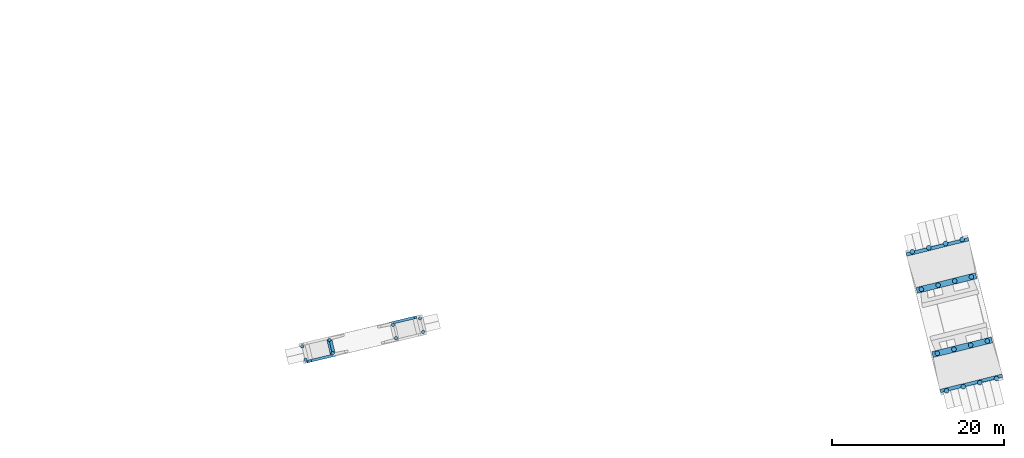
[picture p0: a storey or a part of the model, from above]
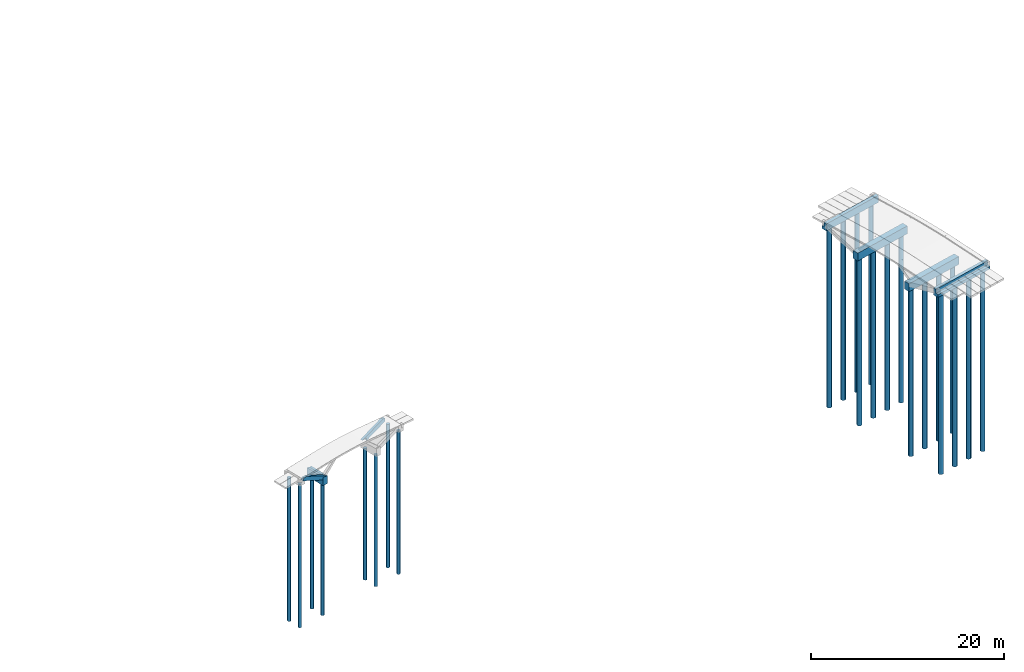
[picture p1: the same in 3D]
Properties of the parts of a building model (IFC2X3), part 1 of 2

# File
Description: ViewDefinition [CoordinationView_V2.0, QuantityTakeOffAddOnView]
File name: 319-150
Time: 2020-09-15T14:20:07
Written by: The EXPRESS Data Manager Version 5.02.0100.07 : 28 Aug 2013
Made in: 20190731_1515(x64) - Exporter 20.1.1.1 - Alternate UI 20.1.1.1
Comment: STEP Physical File produced by: The EXPRESS Data Manager Version 5.02.0100.07 : 28 Aug 2013 * Module: EDMstepFileFactory/EDMstandAlone * Creation date: Tue Sep 15 14:20:07 2020 * Host: PBT03-246 * Database: C:\Users\jeshol\AppData\Local\Temp\80c4dca2-110f-446d-8571-baf07fbfbc19\114c5863-edfc-40fc-962f-66e0f54f50cc\ifc * Database version: 5507 * Database creation date: Tue Sep 15 14:19:58 2020 * Schema: IFC2X3 * Model: DataRepository.ifc * Model creation date: Tue Sep 15 14:19:59 2020 * Header model: DataRepository.ifc_HeaderModel * Header model creation date: Tue Sep 15 14:19:59 2020 * EDMuser: sdai-user * EDMgroup: sdai-group * License ID and type: 5605 : Permanent license. Expiry date: * EDMstepFileFactory options: 020000

# IfcProject, 319-150
LongName: Bruggen Achterburggracht Machinesloot; Phase: Technisch Ontwerp

# IfcSite, Bruggen Achterburggracht Machinesloot
RefLatitude: 52, 22, 22, 799999; RefLongitude: 4, 53, 41, 279999; RefElevation: 0 mm

# IfcBuilding, Bruggen Achterburggracht Machinesloot
LongName: Bruggen Achterburggracht Machinesloot
Pset_Pieters_project informatie - Project Name: Bruggen Achterburggracht Machinesloot; Project Number: 319-150; Client Name: Gemeente Langedijk; Project Status: Technisch Ontwerp; Project Issue Date: 15-09-2020; model van: Pieters Bouwtechniek Delft; model status: Constructiefmodel; website: www.pietersbouwtechniek.nl; projectleider: S. Janssen; modelleur: Pieters Bouwtechniek Delft
Pset_ProductRequirements - Category: Project Information
Pset_BuildingCommon - NumberOfStoreys: 1

# IfcBuildingStorey: Level:PBT_level, 00 begane grond
In: Bruggen Achterburggracht Machinesloot
LongName: NAP; Elevation: 2.70717e-13 mm
Pset_AirSideSystemInformation - Name: palenplan
Pset_ProductRequirements - Name: palenplan; Category: Levels

# IfcBuildingElementProxy: Brug 2 kolom, Brug 2 kolom1:Brug 2 kolom:1546321
In: 00 begane grond
Type - Material: 00_PBT_MAT_beton t.p.g.
Type - Pset_BuildingElementProxyCommon - Reference: Brug 2 kolom1:Brug 2 kolom
Type - Pset_ProductRequirements - Category: Structural Framing
Type - Pset_QuantityTakeOff - Reference: Brug 2 kolom1:Brug 2 kolom
Pset_BuildingElementProxyCommon - sets with these values: 2
Phasing - Phase Created: Nieuw
Pset_Pieters - Naam: Brug 2 kolom1: Brug 2 kolom; Type: Brug 2 kolom1: Brug 2 kolom; Fase: gecreeerd: Nieuw

# IfcBuildingElementProxy: Brug 2 kolom, Brug 2 kolom2:Brug 2 kolom:1549490
In: 00 begane grond
Type - Material: 00_PBT_MAT_beton t.p.g.
Type - Pset_BuildingElementProxyCommon - Reference: Brug 2 kolom2:Brug 2 kolom
Type - Pset_ProductRequirements - Category: Structural Framing
Type - Pset_QuantityTakeOff - Reference: Brug 2 kolom2:Brug 2 kolom
Pset_BuildingElementProxyCommon - sets with these values: 2
Phasing - Phase Created: Nieuw
Pset_Pieters - Naam: Brug 2 kolom2: Brug 2 kolom; Type: Brug 2 kolom2: Brug 2 kolom; Fase: gecreeerd: Nieuw

# IfcBuildingElementProxy: Brug 2 kolom, Brug 2 kolom3:Brug 2 kolom:1563801
In: 00 begane grond
Type - Material: 00_PBT_MAT_beton t.p.g.
Type - Pset_BuildingElementProxyCommon - Reference: Brug 2 kolom3:Brug 2 kolom
Type - Pset_ProductRequirements - Category: Structural Framing
Type - Pset_QuantityTakeOff - Reference: Brug 2 kolom3:Brug 2 kolom
Pset_BuildingElementProxyCommon - sets with these values: 2
Phasing - Phase Created: Nieuw
Pset_Pieters - Naam: Brug 2 kolom3: Brug 2 kolom; Type: Brug 2 kolom3: Brug 2 kolom; Fase: gecreeerd: Nieuw

# IfcBuildingElementProxy: Brug 2 kolom, Brug 2 kolom4:Brug 2 kolom:1563828
In: 00 begane grond
Type - Material: 00_PBT_MAT_beton t.p.g.
Type - Pset_BuildingElementProxyCommon - Reference: Brug 2 kolom4:Brug 2 kolom
Type - Pset_ProductRequirements - Category: Structural Framing
Type - Pset_QuantityTakeOff - Reference: Brug 2 kolom4:Brug 2 kolom
Pset_BuildingElementProxyCommon - sets with these values: 2
Phasing - Phase Created: Nieuw
Pset_Pieters - Naam: Brug 2 kolom4: Brug 2 kolom; Type: Brug 2 kolom4: Brug 2 kolom; Fase: gecreeerd: Nieuw

# IfcBuildingElementProxy: Brug 2 wand, Brug 2 wand1:Brug 2 wand:1549459
In: 00 begane grond
Type - Material: 00_PBT_MAT_beton t.p.g.
Type - Pset_BuildingElementProxyCommon - Reference: Brug 2 wand1:Brug 2 wand
Type - Pset_ProductRequirements - Category: Structural Framing
Type - Pset_QuantityTakeOff - Reference: Brug 2 wand1:Brug 2 wand
Pset_BuildingElementProxyCommon - sets with these values: 2
Phasing - Phase Created: Nieuw
Pset_Pieters - Naam: Brug 2 wand1: Brug 2 wand; Type: Brug 2 wand1: Brug 2 wand; Fase: gecreeerd: Nieuw; Structural Material: 00_PBT_MAT_beton t.p.g.

# IfcBuildingElementProxy: Brug 2 wand, Brug 2 wand:Brug 2 wand:1545229
In: 00 begane grond
Type - Material: 00_PBT_MAT_beton t.p.g.
Type - Pset_BuildingElementProxyCommon - Reference: Brug 2 wand:Brug 2 wand
Type - Pset_ProductRequirements - Category: Structural Framing
Type - Pset_QuantityTakeOff - Reference: Brug 2 wand:Brug 2 wand
Pset_BuildingElementProxyCommon - sets with these values: 2
Phasing - Phase Created: Nieuw
Pset_Pieters - Naam: Brug 2 wand: Brug 2 wand; Type: Brug 2 wand: Brug 2 wand; Fase: gecreeerd: Nieuw; Structural Material: 00_PBT_MAT_beton t.p.g.

# IfcBuildingElementProxy: Brug 4 kolom/wand, Brug 4 kolom/wand1:Brug 4 kolom/wand:1635152
In: 00 begane grond
Type - Material: 00_PBT_MAT_beton t.p.g.
Type - Pset_BuildingElementProxyCommon - Reference: Brug 4 kolom/wand1:Brug 4 kolom/wand
Type - Pset_ProductRequirements - Category: Structural Framing
Type - Pset_QuantityTakeOff - Reference: Brug 4 kolom/wand1:Brug 4 kolom/wand
Pset_BuildingElementProxyCommon - sets with these values: 2
Phasing - Phase Created: Nieuw
Pset_Pieters - Naam: Brug 4 kolom/wand1: Brug 4 kolom/wand; Type: Brug 4 kolom/wand1: Brug 4 kolom/wand; Fase: gecreeerd: Nieuw

# IfcBuildingElementProxy: Brug 4 kolom/wand, Brug 4 kolom/wand2:Brug 4 kolom/wand:1885352
In: 00 begane grond
Type - Material: 00_PBT_MAT_beton t.p.g.
Type - Pset_BuildingElementProxyCommon - Reference: Brug 4 kolom/wand2:Brug 4 kolom/wand
Type - Pset_ProductRequirements - Category: Structural Framing
Type - Pset_QuantityTakeOff - Reference: Brug 4 kolom/wand2:Brug 4 kolom/wand
Pset_BuildingElementProxyCommon - sets with these values: 2
Phasing - Phase Created: Nieuw
Pset_Pieters - Naam: Brug 4 kolom/wand2: Brug 4 kolom/wand; Type: Brug 4 kolom/wand2: Brug 4 kolom/wand; Fase: gecreeerd: Nieuw

# IfcBuildingElementProxy: Brug 4 kolom/wand, Brug 4 kolom/wand:Brug 4 kolom/wand:1607215
In: 00 begane grond
Type - Material: 00_PBT_MAT_beton t.p.g.
Type - Pset_BuildingElementProxyCommon - Reference: Brug 4 kolom/wand:Brug 4 kolom/wand
Type - Pset_ProductRequirements - Category: Structural Framing
Type - Pset_QuantityTakeOff - Reference: Brug 4 kolom/wand:Brug 4 kolom/wand
Pset_BuildingElementProxyCommon - sets with these values: 2
Phasing - Phase Created: Nieuw
Pset_Pieters - Naam: Brug 4 kolom/wand: Brug 4 kolom/wand; Type: Brug 4 kolom/wand: Brug 4 kolom/wand; Fase: gecreeerd: Nieuw

# IfcBuildingElementProxy: brug 1 vleugelwand, brug 1 vleugelwand2:brug 1 vleugelwand:1730079
In: 00 begane grond
Type - Material: 00_PBT_MAT_beton t.p.g.
Type - Pset_BuildingElementProxyCommon - Reference: brug 1 vleugelwand2:brug 1 vleugelwand
Type - Pset_ProductRequirements - Category: Structural Framing
Type - Pset_QuantityTakeOff - Reference: brug 1 vleugelwand2:brug 1 vleugelwand
Pset_BuildingElementProxyCommon - sets with these values: 2
Phasing - Phase Created: Nieuw
Pset_Pieters - Naam: brug 1 vleugelwand2: brug 1 vleugelwand; Type: brug 1 vleugelwand2: brug 1 vleugelwand; Fase: gecreeerd: Nieuw; Structural Material: 00_PBT_MAT_beton t.p.g.

# IfcBuildingElementProxy: brug 1 vleugelwand, brug 1 vleugelwand3:brug 1 vleugelwand:1754347
In: 00 begane grond
Type - Material: 00_PBT_MAT_beton t.p.g.
Type - Pset_BuildingElementProxyCommon - Reference: brug 1 vleugelwand3:brug 1 vleugelwand
Type - Pset_ProductRequirements - Category: Structural Framing
Type - Pset_QuantityTakeOff - Reference: brug 1 vleugelwand3:brug 1 vleugelwand
Pset_BuildingElementProxyCommon - sets with these values: 2
Phasing - Phase Created: Nieuw
Pset_Pieters - Naam: brug 1 vleugelwand3: brug 1 vleugelwand; Type: brug 1 vleugelwand3: brug 1 vleugelwand; Fase: gecreeerd: Nieuw; Structural Material: 00_PBT_MAT_beton t.p.g.

# IfcBuildingElementProxy: brug 1 vleugelwand, brug 1 vleugelwand4:brug 1 vleugelwand:1754160
In: 00 begane grond
Type - Material: 00_PBT_MAT_beton t.p.g.
Type - Pset_BuildingElementProxyCommon - Reference: brug 1 vleugelwand4:brug 1 vleugelwand
Type - Pset_ProductRequirements - Category: Structural Framing
Type - Pset_QuantityTakeOff - Reference: brug 1 vleugelwand4:brug 1 vleugelwand
Pset_BuildingElementProxyCommon - sets with these values: 2
Phasing - Phase Created: Nieuw
Pset_Pieters - Naam: brug 1 vleugelwand4: brug 1 vleugelwand; Type: brug 1 vleugelwand4: brug 1 vleugelwand; Fase: gecreeerd: Nieuw; Structural Material: 00_PBT_MAT_beton t.p.g.

# IfcBuildingElementProxy: brug 1 vleugelwand, brug 1 vleugelwand6:brug 1 vleugelwand:1754410
In: 00 begane grond
Type - Material: 00_PBT_MAT_beton t.p.g.
Type - Pset_BuildingElementProxyCommon - Reference: brug 1 vleugelwand6:brug 1 vleugelwand
Type - Pset_ProductRequirements - Category: Structural Framing
Type - Pset_QuantityTakeOff - Reference: brug 1 vleugelwand6:brug 1 vleugelwand
Pset_BuildingElementProxyCommon - sets with these values: 2
Phasing - Phase Created: Nieuw
Pset_Pieters - Naam: brug 1 vleugelwand6: brug 1 vleugelwand; Type: brug 1 vleugelwand6: brug 1 vleugelwand; Fase: gecreeerd: Nieuw; Structural Material: 00_PBT_MAT_beton t.p.g.

# IfcBuildingElementProxy: brug 1 wand 2, brug 1 wand 4:brug 1 wand 2:1732974
In: 00 begane grond
Type - Material: 00_PBT_MAT_beton t.p.g.
Type - Pset_BuildingElementProxyCommon - Reference: brug 1 wand 4:brug 1 wand 2
Type - Pset_ProductRequirements - Category: Structural Framing
Type - Pset_QuantityTakeOff - Reference: brug 1 wand 4:brug 1 wand 2
Pset_BuildingElementProxyCommon - sets with these values: 2
Phasing - Phase Created: Nieuw
Pset_Pieters - Naam: brug 1 wand 4: brug 1 wand 2; Type: brug 1 wand 4: brug 1 wand 2; Fase: gecreeerd: Nieuw; Structural Material: 00_PBT_MAT_beton t.p.g.

# IfcBuildingElementProxy: brug 2 vleugelwand, brug 2 vleugelwand1:brug 2 vleugelwand:1561800
In: 00 begane grond
Type - Material: 00_PBT_MAT_beton t.p.g.
Type - Pset_BuildingElementProxyCommon - Reference: brug 2 vleugelwand1:brug 2 vleugelwand
Type - Pset_ProductRequirements - Category: Structural Framing
Type - Pset_QuantityTakeOff - Reference: brug 2 vleugelwand1:brug 2 vleugelwand
Type - Pset_Pieters - Omschrijving: vleugelwand d=300
Pset_BuildingElementProxyCommon - sets with these values: 2
Phasing - Phase Created: Nieuw
Pset_Pieters - Naam: brug 2 vleugelwand1: brug 2 vleugelwand; Type: brug 2 vleugelwand1: brug 2 vleugelwand; Fase: gecreeerd: Nieuw; Structural Material: 00_PBT_MAT_beton t.p.g.

# IfcBuildingElementProxy: brug 2 vleugelwand, brug 2 vleugelwand:brug 2 vleugelwand:1550577
In: 00 begane grond
Type - Material: 00_PBT_MAT_beton t.p.g.
Type - Pset_BuildingElementProxyCommon - Reference: brug 2 vleugelwand:brug 2 vleugelwand
Type - Pset_ProductRequirements - Category: Structural Framing
Type - Pset_QuantityTakeOff - Reference: brug 2 vleugelwand:brug 2 vleugelwand
Type - Pset_Pieters - Omschrijving: vleugelwand d=300
Pset_BuildingElementProxyCommon - sets with these values: 2
Phasing - Phase Created: Nieuw
Pset_Pieters - Naam: brug 2 vleugelwand: brug 2 vleugelwand; Type: brug 2 vleugelwand: brug 2 vleugelwand; Fase: gecreeerd: Nieuw; Structural Material: 00_PBT_MAT_beton t.p.g.

# IfcBuildingElementProxy: brug 2 vleugelwand 2, brug 2 vleugelwand 1:brug 2 vleugelwand 2:1561916
In: 00 begane grond
Type - Material: 00_PBT_MAT_beton t.p.g.
Type - Pset_BuildingElementProxyCommon - Reference: brug 2 vleugelwand 1:brug 2 vleugelwand 2
Type - Pset_ProductRequirements - Category: Structural Framing
Type - Pset_QuantityTakeOff - Reference: brug 2 vleugelwand 1:brug 2 vleugelwand 2
Type - Pset_Pieters - Omschrijving: vleugelwand d=300
Pset_BuildingElementProxyCommon - sets with these values: 2
Phasing - Phase Created: Nieuw
Pset_Pieters - Naam: brug 2 vleugelwand 1: brug 2 vleugelwand 2; Type: brug 2 vleugelwand 1: brug 2 vleugelwand 2; Fase: gecreeerd: Nieuw; Structural Material: 00_PBT_MAT_beton t.p.g.

# IfcBuildingElementProxy: brug 2 vleugelwand 2, brug 2 vleugelwand 2:brug 2 vleugelwand 2:1553450
In: 00 begane grond
Type - Material: 00_PBT_MAT_beton t.p.g.
Type - Pset_BuildingElementProxyCommon - Reference: brug 2 vleugelwand 2:brug 2 vleugelwand 2
Type - Pset_ProductRequirements - Category: Structural Framing
Type - Pset_QuantityTakeOff - Reference: brug 2 vleugelwand 2:brug 2 vleugelwand 2
Pset_BuildingElementProxyCommon - sets with these values: 2
Phasing - Phase Created: Nieuw
Pset_Pieters - Naam: brug 2 vleugelwand 2: brug 2 vleugelwand 2; Type: brug 2 vleugelwand 2: brug 2 vleugelwand 2; Fase: gecreeerd: Nieuw; Structural Material: 00_PBT_MAT_beton t.p.g.

# IfcBuildingElementProxy: brug 4 wand, brug 4 wand1:brug 4 wand:1635213
In: 00 begane grond
Type - Material: 00_PBT_MAT_beton t.p.g.
Type - Pset_BuildingElementProxyCommon - Reference: brug 4 wand1:brug 4 wand
Type - Pset_ProductRequirements - Category: Structural Framing
Type - Pset_QuantityTakeOff - Reference: brug 4 wand1:brug 4 wand
Pset_BuildingElementProxyCommon - sets with these values: 2
Phasing - Phase Created: Nieuw
Pset_Pieters - Naam: brug 4 wand1: brug 4 wand; Type: brug 4 wand1: brug 4 wand; Fase: gecreeerd: Nieuw

# IfcBuildingElementProxy: brug 4 wand, brug 4 wand:brug 4 wand:1624354
In: 00 begane grond
Type - Material: 00_PBT_MAT_beton t.p.g.
Type - Pset_BuildingElementProxyCommon - Reference: brug 4 wand:brug 4 wand
Type - Pset_ProductRequirements - Category: Structural Framing
Type - Pset_QuantityTakeOff - Reference: brug 4 wand:brug 4 wand
Pset_BuildingElementProxyCommon - sets with these values: 2
Phasing - Phase Created: Nieuw
Pset_Pieters - Naam: brug 4 wand: brug 4 wand; Type: brug 4 wand: brug 4 wand; Fase: gecreeerd: Nieuw

# IfcBuildingElementProxy: kolom brug 3 .2, kolom brug 3 .1:kolom brug 3 .2:1430988
In: 00 begane grond
Type - Material: 00_PBT_MAT_beton t.p.g.
Type - Pset_BuildingElementProxyCommon - Reference: kolom brug 3 .1:kolom brug 3 .2
Type - Pset_ProductRequirements - Category: Structural Framing
Type - Pset_QuantityTakeOff - Reference: kolom brug 3 .1:kolom brug 3 .2
Pset_BuildingElementProxyCommon - sets with these values: 2
Phasing - Phase Created: Nieuw
Pset_Pieters - Naam: kolom brug 3 .1: kolom brug 3 .2; Type: kolom brug 3 .1: kolom brug 3 .2; Fase: gecreeerd: Nieuw

# IfcBuildingElementProxy: kolom brug 3 .2, kolom brug 3 .2:kolom brug 3 .2:1468975
In: 00 begane grond
Type - Material: 00_PBT_MAT_beton t.p.g.
Type - Pset_BuildingElementProxyCommon - Reference: kolom brug 3 .2:kolom brug 3 .2
Type - Pset_ProductRequirements - Category: Structural Framing
Type - Pset_QuantityTakeOff - Reference: kolom brug 3 .2:kolom brug 3 .2
Pset_BuildingElementProxyCommon - sets with these values: 2
Phasing - Phase Created: Nieuw
Pset_Pieters - Naam: kolom brug 3 .2: kolom brug 3 .2; Type: kolom brug 3 .2: kolom brug 3 .2; Fase: gecreeerd: Nieuw

# IfcBuildingElementProxy: kolom brug 3 .2, kolom brug 3 .4:kolom brug 3 .2:1464659
In: 00 begane grond
Type - Material: 00_PBT_MAT_beton t.p.g.
Type - Pset_BuildingElementProxyCommon - Reference: kolom brug 3 .4:kolom brug 3 .2
Type - Pset_ProductRequirements - Category: Structural Framing
Type - Pset_QuantityTakeOff - Reference: kolom brug 3 .4:kolom brug 3 .2
Pset_BuildingElementProxyCommon - sets with these values: 2
Phasing - Phase Created: Nieuw
Pset_Pieters - Naam: kolom brug 3 .4: kolom brug 3 .2; Type: kolom brug 3 .4: kolom brug 3 .2; Fase: gecreeerd: Nieuw

# IfcBuildingElementProxy: kolom brug 3 .2, kolom brug 3 .5:kolom brug 3 .2:1469002
In: 00 begane grond
Type - Material: 00_PBT_MAT_beton t.p.g.
Type - Pset_BuildingElementProxyCommon - Reference: kolom brug 3 .5:kolom brug 3 .2
Type - Pset_ProductRequirements - Category: Structural Framing
Type - Pset_QuantityTakeOff - Reference: kolom brug 3 .5:kolom brug 3 .2
Pset_BuildingElementProxyCommon - sets with these values: 2
Phasing - Phase Created: Nieuw
Pset_Pieters - Naam: kolom brug 3 .5: kolom brug 3 .2; Type: kolom brug 3 .5: kolom brug 3 .2; Fase: gecreeerd: Nieuw

# IfcBuildingElementProxy: wand brug 3, wand brug 1:wand brug 3:1498558
In: 00 begane grond
Type - Material: 00_PBT_MAT_beton t.p.g.
Type - Pset_BuildingElementProxyCommon - Reference: wand brug 1:wand brug 3
Type - Pset_ProductRequirements - Category: Structural Framing
Type - Pset_QuantityTakeOff - Reference: wand brug 1:wand brug 3
Pset_BuildingElementProxyCommon - sets with these values: 2
Phasing - Phase Created: Nieuw
Pset_Pieters - Naam: wand brug 1: wand brug 3; Type: wand brug 1: wand brug 3; Fase: gecreeerd: Nieuw

# IfcBuildingElementProxy: wand brug 3, wand brug 3:wand brug 3:1432832
In: 00 begane grond
Type - Material: 00_PBT_MAT_beton t.p.g.
Type - Pset_BuildingElementProxyCommon - Reference: wand brug 3:wand brug 3
Type - Pset_ProductRequirements - Category: Structural Framing
Type - Pset_QuantityTakeOff - Reference: wand brug 3:wand brug 3
Pset_BuildingElementProxyCommon - sets with these values: 2
Phasing - Phase Created: Nieuw
Pset_Pieters - Naam: wand brug 3: wand brug 3; Type: wand brug 3: wand brug 3; Fase: gecreeerd: Nieuw

# IfcFooting: 16_PBT_SFO_beton_poer:600x600x400 (3)
In: 00 begane grond
Classification: 16.13 funderingsconstructies - voeten en balken, fundatie poeren (Uniformat); Material: 00_PBT_MAT_beton t.p.g.
Pset_ProductRequirements - Category: Structural Foundations
Pset_QuantityTakeOff - Reference: 16_PBT_SFO_beton_poer:600x600x400
Pset_ReinforcementBarCountOfIndependentFooting - Description: 600x600x400; Reference: 16_PBT_SFO_beton_poer:600x600x400; sets with these values: 2
Phasing - Phase Created: Nieuw
Pset_Pieters - Naam: 16_PBT_SFO_beton_poer: 600x600x400; Type: 16_PBT_SFO_beton_poer: 600x600x400; NL/SfB: 16.13; NL/SfB omschrijving: funderingsconstructies - voeten en balken, fundatie poeren; Fase: gecreeerd: Nieuw; Dikte: 400 mm; Lengte: 600 mm; Breedte: 600 mm; Omschrijving: 600x600x400; Structural Material: 00_PBT_MAT_beton t.p.g.
Name (16_PBT_SFO_beton_poer:600x600x400:...) | Verdieping | Offset tov verdieping (mm)
1839577 | Level: NAP | -860
1880632 | Level: PEIL=NAP | -590
1881418 | Level: PEIL=NAP | -590

# IfcFooting: 16_PBT_SF_funderingsbalk enkele sponning:Brug 1_700x1000 (2)
In: 00 begane grond
Classification: 16.12 funderingsconstructies - voeten en balken, fundatie balken (Uniformat); Material: 00_PBT_MAT_beton t.p.g.
Pset_ProductRequirements - Category: Structural Framing
Pset_QuantityTakeOff - Reference: 16_PBT_SF_funderingsbalk enkele sponning:Brug 1_700x1000
Pset_ReinforcementBarCountOfIndependentFooting - Description: 700x1000; Reference: 16_PBT_SF_funderingsbalk enkele sponning:Brug 1_700x1000; sets with these values: 2
Phasing - Phase Created: Nieuw
Pset_Pieters - Naam: 16_PBT_SF_funderingsbalk enkele sponning: Brug 1_700x1000; Type: 16_PBT_SF_funderingsbalk enkele sponning: Brug 1_700x1000; NL/SfB: 16.12; NL/SfB omschrijving: funderingsconstructies - voeten en balken, fundatie balken; Fase: gecreeerd: Nieuw; Verdieping: Level: PEIL=NAP; Offset tov verdieping zijde 1: -1350 mm; Offset tov verdieping zijde 2: -1350 mm; Lengte: 7880 mm; Hoogte: 1000 mm; Breedte: 700 mm; Omschrijving: 700x1000; Structural Material: 00_PBT_MAT_beton t.p.g.
Name (16_PBT_SF_funderingsbalk enkele sponning:Brug 1_700x1000:...)
1732956
1733404

# IfcFooting: 16_PBT_SF_funderingsbalk enkele sponning:Brug 2_600x1000 (2)
In: 00 begane grond
Classification: 16.12 funderingsconstructies - voeten en balken, fundatie balken (Uniformat); Material: 00_PBT_MAT_beton t.p.g.
Pset_ProductRequirements - Category: Structural Framing
Pset_QuantityTakeOff - Reference: 16_PBT_SF_funderingsbalk enkele sponning:Brug 2_600x1000
Pset_ReinforcementBarCountOfIndependentFooting - Description: 600x1000; Reference: 16_PBT_SF_funderingsbalk enkele sponning:Brug 2_600x1000; sets with these values: 2
Phasing - Phase Created: Nieuw
Pset_Pieters - Naam: 16_PBT_SF_funderingsbalk enkele sponning: Brug 2_600x1000; Type: 16_PBT_SF_funderingsbalk enkele sponning: Brug 2_600x1000; NL/SfB: 16.12; NL/SfB omschrijving: funderingsconstructies - voeten en balken, fundatie balken; Fase: gecreeerd: Nieuw; Verdieping: Level: PEIL=NAP; Offset tov verdieping zijde 1: -1070 mm; Offset tov verdieping zijde 2: -1070 mm; Lengte: 3600 mm; Hoogte: 1280 mm; Breedte: 600 mm; Omschrijving: 600x1000; Structural Material: 00_PBT_MAT_beton t.p.g.
Name (16_PBT_SF_funderingsbalk enkele sponning:Brug 2_600x1000:...)
1539882
1549444

# IfcFooting: 16_PBT_SF_funderingsbalk enkele sponning:Brug 3_600x1000 (2)
In: 00 begane grond
Classification: 16.12 funderingsconstructies - voeten en balken, fundatie balken (Uniformat); Material: 00_PBT_MAT_beton t.p.g.
Pset_ProductRequirements - Category: Structural Framing
Pset_QuantityTakeOff - Reference: 16_PBT_SF_funderingsbalk enkele sponning:Brug 3_600x1000
Pset_ReinforcementBarCountOfIndependentFooting - Description: 600x1000; Reference: 16_PBT_SF_funderingsbalk enkele sponning:Brug 3_600x1000; sets with these values: 2
Phasing - Phase Created: Nieuw
Pset_Pieters - Naam: 16_PBT_SF_funderingsbalk enkele sponning: Brug 3_600x1000; Type: 16_PBT_SF_funderingsbalk enkele sponning: Brug 3_600x1000; NL/SfB: 16.12; NL/SfB omschrijving: funderingsconstructies - voeten en balken, fundatie balken; Fase: gecreeerd: Nieuw; Verdieping: Level: PEIL=NAP; Offset tov verdieping zijde 1: -1290 mm; Offset tov verdieping zijde 2: -1290 mm; Lengte: 2400 mm; Hoogte: 1060 mm; Breedte: 600 mm; Omschrijving: 600x1000; Structural Material: 00_PBT_MAT_beton t.p.g.
Name (16_PBT_SF_funderingsbalk enkele sponning:Brug 3_600x1000:...)
1444405
1464684

# IfcFooting: 16_PBT_SF_funderingsbalk enkele sponning:Brug 4_700x1000 (2)
In: 00 begane grond
Classification: 16.12 funderingsconstructies - voeten en balken, fundatie balken (Uniformat); Material: 00_PBT_MAT_beton t.p.g.
Pset_ProductRequirements - Category: Structural Framing
Pset_QuantityTakeOff - Reference: 16_PBT_SF_funderingsbalk enkele sponning:Brug 4_700x1000
Pset_ReinforcementBarCountOfIndependentFooting - Description: 700x1000; Reference: 16_PBT_SF_funderingsbalk enkele sponning:Brug 4_700x1000; sets with these values: 2
Phasing - Phase Created: Nieuw
Pset_Pieters - Naam: 16_PBT_SF_funderingsbalk enkele sponning: Brug 4_700x1000; Type: 16_PBT_SF_funderingsbalk enkele sponning: Brug 4_700x1000; NL/SfB: 16.12; NL/SfB omschrijving: funderingsconstructies - voeten en balken, fundatie balken; Fase: gecreeerd: Nieuw; Verdieping: Level: PEIL=NAP; Offset tov verdieping zijde 1: -1350 mm; Offset tov verdieping zijde 2: -1350 mm; Lengte: 7140 mm; Hoogte: 1000 mm; Breedte: 700 mm; Omschrijving: 700x1000; Structural Material: 00_PBT_MAT_beton t.p.g.
Name (16_PBT_SF_funderingsbalk enkele sponning:Brug 4_700x1000:...)
1608725
1635157

# IfcFooting: 16_PBT_SF_funderingsbalk:300x500 i.h.w.g. (4)
In: 00 begane grond
Classification: 16.12 funderingsconstructies - voeten en balken, fundatie balken (Uniformat); Material: 00_PBT_MAT_beton t.p.g.
Pset_ProductRequirements - Category: Structural Framing
Pset_QuantityTakeOff - Reference: 16_PBT_SF_funderingsbalk:300x500 i.h.w.g.; sets with these values: 3
Phasing - Phase Created: Nieuw
Pset_Pieters - Naam: 16_PBT_SF_funderingsbalk: 300x500 i.h.w.g.; Type: 16_PBT_SF_funderingsbalk: 300x500 i.h.w.g.; NL/SfB: 16.12; NL/SfB omschrijving: funderingsconstructies - voeten en balken, fundatie balken; Fase: gecreeerd: Nieuw; Verdieping: Level: NAP; Offset tov verdieping zijde 1: -1350 mm; Offset tov verdieping zijde 2: 100.772 mm; Lengte: 3566.86 mm; Hoogte: 500 mm; Breedte: 300 mm; Structural Material: 00_PBT_MAT_beton t.p.g.
Name (16_PBT_SF_funderingsbalk:300x500 i.h.w.g.:...)
1808836
1809368
1809411
1809416

# IfcFooting: 319-150_brugdek 1_verkeersbrug:brugdek 1_verkeersbrug_vorm niet aanpasbaar, 319-150_brugdek 1_verkeersbrug:brugdek 1_verkeersbrug_vorm niet aanpasbaar:1402137
In: 00 begane grond
Classification: 23.20 vloeren - constructief, algemeen (verzamelniveau) (Uniformat); Material: 00_PBT_MAT_beton t.p.g.
Pset_ProductRequirements - Category: Structural Foundations
Pset_QuantityTakeOff - Reference: 319-150_brugdek 1_verkeersbrug:brugdek 1_verkeersbrug_vorm niet aanpasbaar
Pset_ReinforcementBarCountOfIndependentFooting - Description: d=320; Reference: 319-150_brugdek 1_verkeersbrug:brugdek 1_verkeersbrug_vorm niet aanpasbaar; sets with these values: 2
Phasing - Phase Created: Nieuw
Pset_Pieters - Naam: 319-150_brugdek 1_verkeersbrug: brugdek 1_verkeersbrug_vorm niet aanpasbaar; Type: 319-150_brugdek 1_verkeersbrug: brugdek 1_verkeersbrug_vorm niet aanpasbaar; NL/SfB: 23.20; NL/SfB omschrijving: vloeren - constructief, algemeen (verzamelniveau); Fase: gecreeerd: Nieuw; Verdieping: Level: NAP; Offset tov verdieping: 470 mm; Lengte: 2500 mm; Breedte: 2500 mm; Omschrijving: d=320; Structural Material: 00_PBT_MAT_beton t.p.g.

# IfcFooting: 319-150_brugdek 2_fietsbrug:brugdek 2_fietsbrug_vorm niet aanpasbaar, 319-150_brugdek 2_fietsbrug:brugdek 2_fietsbrug_vorm niet aanpasbaar:1508879
In: 00 begane grond
Classification: 23.20 vloeren - constructief, algemeen (verzamelniveau) (Uniformat); Material: 00_PBT_MAT_beton t.p.g.
Pset_ProductRequirements - Category: Structural Foundations
Pset_QuantityTakeOff - Reference: 319-150_brugdek 2_fietsbrug:brugdek 2_fietsbrug_vorm niet aanpasbaar
Pset_ReinforcementBarCountOfIndependentFooting - Description: d=230; Reference: 319-150_brugdek 2_fietsbrug:brugdek 2_fietsbrug_vorm niet aanpasbaar; sets with these values: 2
Phasing - Phase Created: Nieuw
Pset_Pieters - Naam: 319-150_brugdek 2_fietsbrug: brugdek 2_fietsbrug_vorm niet aanpasbaar; Type: 319-150_brugdek 2_fietsbrug: brugdek 2_fietsbrug_vorm niet aanpasbaar; NL/SfB: 23.20; NL/SfB omschrijving: vloeren - constructief, algemeen (verzamelniveau); Fase: gecreeerd: Nieuw; Verdieping: Level: PEIL=NAP; Offset tov verdieping: 380 mm; Lengte: 2500 mm; Breedte: 2500 mm; Omschrijving: d=230; Structural Material: 00_PBT_MAT_beton t.p.g.

# IfcFooting: 319-150_brugdek 3 _loopbrug:brugdek 3_loopbrug_vorm niet aanpasbaar, 319-150_brugdek 3 _loopbrug:brugdek 3_loopbrug_vorm niet aanpasbaar:1397991
In: 00 begane grond
Classification: 23.20 vloeren - constructief, algemeen (verzamelniveau) (Uniformat); Material: 00_PBT_MAT_beton t.p.g.
Pset_ProductRequirements - Category: Structural Foundations
Pset_QuantityTakeOff - Reference: 319-150_brugdek 3 _loopbrug:brugdek 3_loopbrug_vorm niet aanpasbaar
Pset_ReinforcementBarCountOfIndependentFooting - Description: d=220; Reference: 319-150_brugdek 3 _loopbrug:brugdek 3_loopbrug_vorm niet aanpasbaar; sets with these values: 2
Phasing - Phase Created: Nieuw
Pset_Pieters - Naam: 319-150_brugdek 3 _loopbrug: brugdek 3_loopbrug_vorm niet aanpasbaar; Type: 319-150_brugdek 3 _loopbrug: brugdek 3_loopbrug_vorm niet aanpasbaar; NL/SfB: 23.20; NL/SfB omschrijving: vloeren - constructief, algemeen (verzamelniveau); Fase: gecreeerd: Nieuw; Verdieping: Level: NAP; Offset tov verdieping: 370 mm; Lengte: 2500 mm; Breedte: 2500 mm; Omschrijving: d=220; Structural Material: 00_PBT_MAT_beton t.p.g.

# IfcFooting: 319-150_brugdek 4_verkeersbrug:brugdek 4_verkeersbrug_vorm niet aanpasbaar, 319-150_brugdek 4_verkeersbrug:brugdek 4_verkeersbrug_vorm niet aanpasbaar:1405200
In: 00 begane grond
Classification: 23.20 vloeren - constructief, algemeen (verzamelniveau) (Uniformat); Material: 00_PBT_MAT_beton t.p.g.
Pset_ProductRequirements - Category: Structural Foundations
Pset_QuantityTakeOff - Reference: 319-150_brugdek 4_verkeersbrug:brugdek 4_verkeersbrug_vorm niet aanpasbaar
Pset_ReinforcementBarCountOfIndependentFooting - Description: d=230; Reference: 319-150_brugdek 4_verkeersbrug:brugdek 4_verkeersbrug_vorm niet aanpasbaar; sets with these values: 2
Phasing - Phase Created: Nieuw
Pset_Pieters - Naam: 319-150_brugdek 4_verkeersbrug: brugdek 4_verkeersbrug_vorm niet aanpasbaar; Type: 319-150_brugdek 4_verkeersbrug: brugdek 4_verkeersbrug_vorm niet aanpasbaar; NL/SfB: 23.20; NL/SfB omschrijving: vloeren - constructief, algemeen (verzamelniveau); Fase: gecreeerd: Nieuw; Verdieping: Level: NAP; Offset tov verdieping: 480 mm; Lengte: 2500 mm; Breedte: 2500 mm; Omschrijving: d=230; Structural Material: 00_PBT_MAT_beton t.p.g.

# IfcFooting: 319-150_funderingsbalk tpv stootplaat:Brug 1_700x1100 (4)
In: 00 begane grond
Classification: 16.12 funderingsconstructies - voeten en balken, fundatie balken (Uniformat); Material: 00_PBT_MAT_beton t.p.g.
Pset_ProductRequirements - Category: Structural Framing
Pset_QuantityTakeOff - Reference: 319-150_funderingsbalk tpv stootplaat:Brug 1_700x1100; sets with these values: 3
Phasing - Phase Created: Nieuw
Pset_Pieters - Naam: 319-150_funderingsbalk tpv stootplaat: Brug 1_700x1100; Type: 319-150_funderingsbalk tpv stootplaat: Brug 1_700x1100; NL/SfB: 16.12; NL/SfB omschrijving: funderingsconstructies - voeten en balken, fundatie balken; Fase: gecreeerd: Nieuw; Offset tov verdieping zijde 1: 240 mm; Offset tov verdieping zijde 2: 240 mm; Lengte: 7800 mm; Hoogte: 1100 mm; Breedte: 700 mm; Structural Material: 00_PBT_MAT_beton t.p.g.
Name (319-150_funderingsbalk tpv stootplaat:Brug 1_700x1100:...) | Verdieping
1676934 | Level: NAP
1732982 | Level: PEIL=NAP
1733430 | Level: PEIL=NAP
1733758 | Level: PEIL=NAP

# IfcFooting: 319-150_funderingsbalk tpv stootplaat:Brug 2_600x850 (2)
In: 00 begane grond
Classification: 16.12 funderingsconstructies - voeten en balken, fundatie balken (Uniformat); Material: 00_PBT_MAT_beton t.p.g.
Pset_ProductRequirements - Category: Structural Framing
Pset_QuantityTakeOff - Reference: 319-150_funderingsbalk tpv stootplaat:Brug 2_600x850
Pset_ReinforcementBarCountOfIndependentFooting - Description: i.h.w.g. beton; Reference: 319-150_funderingsbalk tpv stootplaat:Brug 2_600x850; sets with these values: 2
Phasing - Phase Created: Nieuw
Pset_Pieters - Naam: 319-150_funderingsbalk tpv stootplaat: Brug 2_600x850; Type: 319-150_funderingsbalk tpv stootplaat: Brug 2_600x850; NL/SfB: 16.12; NL/SfB omschrijving: funderingsconstructies - voeten en balken, fundatie balken; Fase: gecreeerd: Nieuw; Offset tov verdieping zijde 1: 260 mm; Offset tov verdieping zijde 2: 260 mm; Hoogte: 850 mm; Breedte: 600 mm; Omschrijving: i.h.w.g. beton; Structural Material: 00_PBT_MAT_beton t.p.g.
Name (319-150_funderingsbalk tpv stootplaat:Brug 2_600x850:...) | Verdieping | Lengte (mm)
1515714 | Level: NAP | 3300
1549442 | Level: PEIL=NAP | 3600

# IfcFooting: 319-150_funderingsbalk tpv stootplaat:Brug 3_700x850 (2)
In: 00 begane grond
Classification: 16.12 funderingsconstructies - voeten en balken, fundatie balken (Uniformat); Material: 00_PBT_MAT_beton t.p.g.
Pset_ProductRequirements - Category: Structural Framing
Pset_QuantityTakeOff - Reference: 319-150_funderingsbalk tpv stootplaat:Brug 3_700x850; sets with these values: 3
Phasing - Phase Created: Nieuw
Pset_Pieters - Naam: 319-150_funderingsbalk tpv stootplaat: Brug 3_700x850; Type: 319-150_funderingsbalk tpv stootplaat: Brug 3_700x850; NL/SfB: 16.12; NL/SfB omschrijving: funderingsconstructies - voeten en balken, fundatie balken; Fase: gecreeerd: Nieuw; Offset tov verdieping zijde 1: -5 mm; Offset tov verdieping zijde 2: -5 mm; Lengte: 2400 mm; Hoogte: 850 mm; Breedte: 700 mm; Structural Material: 00_PBT_MAT_beton t.p.g.
Name (319-150_funderingsbalk tpv stootplaat:Brug 3_700x850:...) | Verdieping
1440072 | Level: NAP
1464682 | Level: PEIL=NAP

# IfcFooting: 319-150_funderingsbalk tpv stootplaat:Brug 4_700x900 (2)
In: 00 begane grond
Classification: 16.12 funderingsconstructies - voeten en balken, fundatie balken (Uniformat); Material: 00_PBT_MAT_beton t.p.g.
Pset_ProductRequirements - Category: Structural Framing
Pset_QuantityTakeOff - Reference: 319-150_funderingsbalk tpv stootplaat:Brug 4_700x900; sets with these values: 3
Phasing - Phase Created: Nieuw
Pset_Pieters - Naam: 319-150_funderingsbalk tpv stootplaat: Brug 4_700x900; Type: 319-150_funderingsbalk tpv stootplaat: Brug 4_700x900; NL/SfB: 16.12; NL/SfB omschrijving: funderingsconstructies - voeten en balken, fundatie balken; Fase: gecreeerd: Nieuw; Offset tov verdieping zijde 1: 170 mm; Offset tov verdieping zijde 2: 170 mm; Lengte: 7500 mm; Hoogte: 900 mm; Breedte: 700 mm; Structural Material: 00_PBT_MAT_beton t.p.g.
Name (319-150_funderingsbalk tpv stootplaat:Brug 4_700x900:...) | Verdieping
1625105 | Level: NAP
1635214 | Level: PEIL=NAP

# IfcPile: 17_PBT_SFO_paal_rond:Ø400 (schroefpaal) brug 1 -1260P -23000NAP 2, 17_PBT_SFO_paal_rond:Ø400 (schroefpaal) brug 1 -1260P -23000NAP 2:1862262
In: 00 begane grond
Classification: 17.21 paalfunderingen - geheid, dragende palen (Uniformat)
Pset_ProductRequirements - Category: Structural Foundations
Pset_QuantityTakeOff - Reference: 17_PBT_SFO_paal_rond:Ø400 (schroefpaal) brug 1 -1260P -23000NAP 2
Phasing - Phase Created: Nieuw
Pset_Pieters - Offset tov verdieping: 0 mm; LoadBearing: yes; IsExternal: yes; Naam: 17_PBT_SFO_paal_rond: Ø400 (schroefpaal) brug 1 -1260P -23000NAP 2; Type: 17_PBT_SFO_paal_rond: Ø400 (schroefpaal) brug 1 -1260P -23000NAP 2; NL/SfB: 17.21; NL/SfB omschrijving: paalfunderingen - geheid, dragende palen; Fase: gecreeerd: Nieuw; Verdieping: Level: PEIL=NAP; Offset tov verdieping (bk wand): 4000 mm; Lengte: 22160 mm; Breedte: 400 mm; Omschrijving: Mortel schroefpaal

# IfcPile: 17_PBT_SFO_paal_rond:Ø400 (schroefpaal) brug 2 -2350P -19000NAP (4)
In: 00 begane grond
Classification: 17.21 paalfunderingen - geheid, dragende palen (Uniformat)
Pset_ProductRequirements - Category: Structural Foundations
Pset_QuantityTakeOff - Reference: 17_PBT_SFO_paal_rond:Ø400 (schroefpaal) brug 2 -2350P -19000NAP
Phasing - Phase Created: Nieuw
Pset_Pieters - Offset tov verdieping: 0 mm; Offset tov verdieping (bk wand): 0 mm; LoadBearing: yes; IsExternal: yes; Naam: 17_PBT_SFO_paal_rond: Ø400 (schroefpaal) brug 2 -2350P -19000NAP; Type: 17_PBT_SFO_paal_rond: Ø400 (schroefpaal) brug 2 -2350P -19000NAP; NL/SfB: 17.21; NL/SfB omschrijving: paalfunderingen - geheid, dragende palen; Fase: gecreeerd: Nieuw; Verdieping: Level: PEIL=NAP; Lengte: 17070 mm; Breedte: 400 mm; Omschrijving: Mortel schroefpaal
Name (17_PBT_SFO_paal_rond:Ø400 (schroefpaal) brug 2 -2350P -19000NAP:...)
1595060
1595062
1596383
1596385

# IfcPile: 17_PBT_SFO_paal_rond:Ø400 (schroefpaal) brug 2 -590P -19000NAP (6)
In: 00 begane grond
Classification: 17.21 paalfunderingen - geheid, dragende palen (Uniformat)
Pset_ProductRequirements - Category: Structural Foundations
Pset_QuantityTakeOff - Reference: 17_PBT_SFO_paal_rond:Ø400 (schroefpaal) brug 2 -590P -19000NAP
Phasing - Phase Created: Nieuw
Pset_Pieters - Naam: 17_PBT_SFO_paal_rond: Ø400 (schroefpaal) brug 2 -590P -19000NAP; Type: 17_PBT_SFO_paal_rond: Ø400 (schroefpaal) brug 2 -590P -19000NAP; NL/SfB: 17.21; NL/SfB omschrijving: paalfunderingen - geheid, dragende palen; Fase: gecreeerd: Nieuw; Offset tov verdieping: 0 mm; Breedte: 400 mm; Omschrijving: Mortel schroefpaal; LoadBearing: yes; IsExternal: yes
Name (17_PBT_SFO_paal_rond:Ø400 (schroefpaal) brug 2 -590P -19000NAP:...) | Verdieping | Offset tov verdieping (bk wand) (mm) | Lengte (mm)
1588683 | Level: NAP | 0 | 18830
1594870 | Level: PEIL=NAP | 0 | 18830
1594968 | Level: PEIL=NAP | 0 | 18830
1594970 | Level: PEIL=NAP | 0 | 18830
1880634 | Level: PEIL=NAP | 4000 | 18430
1881420 | Level: PEIL=NAP | 4000 | 18430

# IfcPile: 17_PBT_SFO_paal_rond:Ø400 (schroefpaal) brug 3 -2350P -19000NAP (4)
In: 00 begane grond
Classification: 17.21 paalfunderingen - geheid, dragende palen (Uniformat)
Pset_ProductRequirements - Category: Structural Foundations
Pset_QuantityTakeOff - Reference: 17_PBT_SFO_paal_rond:Ø400 (schroefpaal) brug 3 -2350P -19000NAP
Phasing - Phase Created: Nieuw
Pset_Pieters - Offset tov verdieping: 0 mm; LoadBearing: yes; IsExternal: yes; Naam: 17_PBT_SFO_paal_rond: Ø400 (schroefpaal) brug 3 -2350P -19000NAP; Type: 17_PBT_SFO_paal_rond: Ø400 (schroefpaal) brug 3 -2350P -19000NAP; NL/SfB: 17.21; NL/SfB omschrijving: paalfunderingen - geheid, dragende palen; Fase: gecreeerd: Nieuw; Verdieping: Level: PEIL=NAP; Offset tov verdieping (bk wand): 4000 mm; Lengte: 17070 mm; Breedte: 400 mm; Omschrijving: Mortel schroefpaal
Name (17_PBT_SFO_paal_rond:Ø400 (schroefpaal) brug 3 -2350P -19000NAP:...)
1597107
1597823
1598252
1598254

# IfcPile: 17_PBT_SFO_paal_rond:Ø400 (schroefpaal) brug 3 -855P -19000NAP (4)
In: 00 begane grond
Classification: 17.21 paalfunderingen - geheid, dragende palen (Uniformat)
Pset_ProductRequirements - Category: Structural Foundations
Pset_QuantityTakeOff - Reference: 17_PBT_SFO_paal_rond:Ø400 (schroefpaal) brug 3 -855P -19000NAP
Phasing - Phase Created: Nieuw
Pset_Pieters - Offset tov verdieping: 0 mm; LoadBearing: yes; IsExternal: yes; Naam: 17_PBT_SFO_paal_rond: Ø400 (schroefpaal) brug 3 -855P -19000NAP; Type: 17_PBT_SFO_paal_rond: Ø400 (schroefpaal) brug 3 -855P -19000NAP; NL/SfB: 17.21; NL/SfB omschrijving: paalfunderingen - geheid, dragende palen; Fase: gecreeerd: Nieuw; Offset tov verdieping (bk wand): 4000 mm; Lengte: 18565 mm; Breedte: 400 mm; Omschrijving: Mortel schroefpaal
Name (17_PBT_SFO_paal_rond:Ø400 (schroefpaal) brug 3 -855P -19000NAP:...) | Verdieping
1596764 | Level: NAP
1597857 | Level: PEIL=NAP
1598250 | Level: PEIL=NAP
1598256 | Level: PEIL=NAP

# IfcPile: 17_PBT_SFO_paal_rond:Ø550 (schroefpaal) brug 1 -2350P -23000NAP (8)
In: 00 begane grond
Classification: 17.21 paalfunderingen - geheid, dragende palen (Uniformat)
Pset_ProductRequirements - Category: Structural Foundations
Pset_QuantityTakeOff - Reference: 17_PBT_SFO_paal_rond:Ø550 (schroefpaal) brug 1 -2350P -23000NAP
Phasing - Phase Created: Nieuw
Pset_Pieters - Offset tov verdieping: 0 mm; LoadBearing: yes; IsExternal: yes; Naam: 17_PBT_SFO_paal_rond: Ø550 (schroefpaal) brug 1 -2350P -23000NAP; Type: 17_PBT_SFO_paal_rond: Ø550 (schroefpaal) brug 1 -2350P -23000NAP; NL/SfB: 17.21; NL/SfB omschrijving: paalfunderingen - geheid, dragende palen; Fase: gecreeerd: Nieuw; Verdieping: Level: PEIL=NAP; Offset tov verdieping (bk wand): 4000 mm; Lengte: 21070 mm; Breedte: 550 mm; Omschrijving: Mortel schroefpaal
Name (17_PBT_SFO_paal_rond:Ø550 (schroefpaal) brug 1 -2350P -23000NAP:...)
1733006
1781650
1781736
1781738
1782187
1782189
1782191
1782193

# IfcPile: 17_PBT_SFO_paal_rond:Ø550 (schroefpaal) brug 1 -860P -23000NAP (8)
In: 00 begane grond
Classification: 17.21 paalfunderingen - geheid, dragende palen (Uniformat)
Pset_ProductRequirements - Category: Structural Foundations
Pset_QuantityTakeOff - Reference: 17_PBT_SFO_paal_rond:Ø550 (schroefpaal) brug 1 -860P -23000NAP
Phasing - Phase Created: Nieuw
Pset_Pieters - Offset tov verdieping: 0 mm; LoadBearing: yes; IsExternal: yes; Naam: 17_PBT_SFO_paal_rond: Ø550 (schroefpaal) brug 1 -860P -23000NAP; Type: 17_PBT_SFO_paal_rond: Ø550 (schroefpaal) brug 1 -860P -23000NAP; NL/SfB: 17.21; NL/SfB omschrijving: paalfunderingen - geheid, dragende palen; Fase: gecreeerd: Nieuw; Verdieping: Level: PEIL=NAP; Offset tov verdieping (bk wand): 4000 mm; Lengte: 22560 mm; Breedte: 550 mm; Omschrijving: Mortel schroefpaal
Name (17_PBT_SFO_paal_rond:Ø550 (schroefpaal) brug 1 -860P -23000NAP:...)
1788932
1788934
1788936
1788938
1790086
1790088
1790090
1790092

# IfcPile: 17_PBT_SFO_paal_rond:Ø550 (schroefpaal) brug 4 -2350P -23500NAP (8)
In: 00 begane grond
Classification: 17.21 paalfunderingen - geheid, dragende palen (Uniformat)
Pset_ProductRequirements - Category: Structural Foundations
Pset_QuantityTakeOff - Reference: 17_PBT_SFO_paal_rond:Ø550 (schroefpaal) brug 4 -2350P -23500NAP
Phasing - Phase Created: Nieuw
Pset_Pieters - Offset tov verdieping: 0 mm; LoadBearing: yes; IsExternal: yes; Naam: 17_PBT_SFO_paal_rond: Ø550 (schroefpaal) brug 4 -2350P -23500NAP; Type: 17_PBT_SFO_paal_rond: Ø550 (schroefpaal) brug 4 -2350P -23500NAP; NL/SfB: 17.21; NL/SfB omschrijving: paalfunderingen - geheid, dragende palen; Fase: gecreeerd: Nieuw; Verdieping: Level: PEIL=NAP; Offset tov verdieping (bk wand): 4000 mm; Lengte: 21570 mm; Breedte: 550 mm; Omschrijving: Mortel schroefpaal
Name (17_PBT_SFO_paal_rond:Ø550 (schroefpaal) brug 4 -2350P -23500NAP:...)
1667277
1667474
1667545
1667558
1667620
1667622
1667624
1667626

# IfcPile: 17_PBT_SFO_paal_rond:Ø550 (schroefpaal) brug 4 -730P -23500NAP (8)
In: 00 begane grond
Classification: 17.21 paalfunderingen - geheid, dragende palen (Uniformat)
Pset_ProductRequirements - Category: Structural Foundations
Pset_QuantityTakeOff - Reference: 17_PBT_SFO_paal_rond:Ø550 (schroefpaal) brug 4 -730P -23500NAP
Phasing - Phase Created: Nieuw
Pset_Pieters - Offset tov verdieping: 0 mm; LoadBearing: yes; IsExternal: yes; Naam: 17_PBT_SFO_paal_rond: Ø550 (schroefpaal) brug 4 -730P -23500NAP; Type: 17_PBT_SFO_paal_rond: Ø550 (schroefpaal) brug 4 -730P -23500NAP; NL/SfB: 17.21; NL/SfB omschrijving: paalfunderingen - geheid, dragende palen; Fase: gecreeerd: Nieuw; Offset tov verdieping (bk wand): 4000 mm; Lengte: 23190 mm; Breedte: 550 mm; Omschrijving: Mortel schroefpaal
Name (17_PBT_SFO_paal_rond:Ø550 (schroefpaal) brug 4 -730P -23500NAP:...) | Verdieping
1666934 | Level: NAP
1667472 | Level: PEIL=NAP
1667543 | Level: PEIL=NAP
1667556 | Level: PEIL=NAP
1667700 | Level: PEIL=NAP
1667702 | Level: PEIL=NAP
1667704 | Level: PEIL=NAP
1667706 | Level: PEIL=NAP

# IfcSlab: Strootplaat 3, Strootplaat 10:Strootplaat 3:1634089
In: 00 begane grond
Type - PredefinedType: FLOOR; Material: 00_PBT_MAT_beton prefab
Type - Pset_ProductRequirements - Category: Floors
Type - Pset_QuantityTakeOff - Reference: Strootplaat 10:Strootplaat 3
Type - Pset_ReinforcementBarPitchOfSlab - Description: stootplaat d=200; Reference: Strootplaat 10:Strootplaat 3
Type - Pset_SlabCommon - IsExternal: no; Reference: Strootplaat 10:Strootplaat 3
Type - Pset_Pieters - Omschrijving: stootplaat d=200
Pset_SlabCommon - PitchAngle: 3 deg
Phasing - Phase Created: Nieuw
Pset_Pieters - Naam: Strootplaat 10: Strootplaat 3; Type: Strootplaat 10: Strootplaat 3; Fase: gecreeerd: Nieuw; Verdieping: Level: PEIL=NAP
BaseQuantities - GrossArea: 0.2375 m2; NetArea: 7.67499 m2; GrossVolume: 712.498 m3; NetVolume: 0.712499 m3; Perimeter: 2400 mm; Width: 2999.99 mm

# IfcSlab: Strootplaat 3, Strootplaat 11:Strootplaat 3:1634109
In: 00 begane grond
Type - PredefinedType: FLOOR; Material: 00_PBT_MAT_beton prefab
Type - Pset_ProductRequirements - Category: Floors
Type - Pset_QuantityTakeOff - Reference: Strootplaat 11:Strootplaat 3
Type - Pset_ReinforcementBarPitchOfSlab - Description: stootplaat d=200; Reference: Strootplaat 11:Strootplaat 3
Type - Pset_SlabCommon - IsExternal: no; Reference: Strootplaat 11:Strootplaat 3
Type - Pset_Pieters - Omschrijving: stootplaat d=200
Pset_SlabCommon - PitchAngle: 3 deg
Phasing - Phase Created: Nieuw
Pset_Pieters - Naam: Strootplaat 11: Strootplaat 3; Type: Strootplaat 11: Strootplaat 3; Fase: gecreeerd: Nieuw; Verdieping: Level: PEIL=NAP
BaseQuantities - GrossArea: 0.2375 m2; NetArea: 7.67499 m2; GrossVolume: 712.498 m3; NetVolume: 0.712499 m3; Perimeter: 2400 mm; Width: 2999.99 mm

# IfcSlab: Strootplaat 3, Strootplaat 12:Strootplaat 3:1634129
In: 00 begane grond
Type - PredefinedType: FLOOR; Material: 00_PBT_MAT_beton prefab
Type - Pset_ProductRequirements - Category: Floors
Type - Pset_QuantityTakeOff - Reference: Strootplaat 12:Strootplaat 3
Type - Pset_ReinforcementBarPitchOfSlab - Description: stootplaat d=200; Reference: Strootplaat 12:Strootplaat 3
Type - Pset_SlabCommon - IsExternal: no; Reference: Strootplaat 12:Strootplaat 3
Type - Pset_Pieters - Omschrijving: stootplaat d=200
Pset_SlabCommon - PitchAngle: 3 deg
Phasing - Phase Created: Nieuw
Pset_Pieters - Naam: Strootplaat 12: Strootplaat 3; Type: Strootplaat 12: Strootplaat 3; Fase: gecreeerd: Nieuw; Verdieping: Level: PEIL=NAP
BaseQuantities - GrossArea: 0.2375 m2; NetArea: 7.67499 m2; GrossVolume: 712.498 m3; NetVolume: 0.712499 m3; Perimeter: 2400 mm; Width: 2999.99 mm

# IfcSlab: Strootplaat 3, Strootplaat 13:Strootplaat 3:1634149
In: 00 begane grond
Type - PredefinedType: FLOOR; Material: 00_PBT_MAT_beton prefab
Type - Pset_ProductRequirements - Category: Floors
Type - Pset_QuantityTakeOff - Reference: Strootplaat 13:Strootplaat 3
Type - Pset_ReinforcementBarPitchOfSlab - Description: stootplaat d=200; Reference: Strootplaat 13:Strootplaat 3
Type - Pset_SlabCommon - IsExternal: no; Reference: Strootplaat 13:Strootplaat 3
Type - Pset_Pieters - Omschrijving: stootplaat d=200
Pset_SlabCommon - PitchAngle: 3 deg
Phasing - Phase Created: Nieuw
Pset_Pieters - Naam: Strootplaat 13: Strootplaat 3; Type: Strootplaat 13: Strootplaat 3; Fase: gecreeerd: Nieuw; Verdieping: Level: PEIL=NAP
BaseQuantities - GrossArea: 0.2375 m2; NetArea: 7.67499 m2; GrossVolume: 712.498 m3; NetVolume: 0.712499 m3; Perimeter: 2400 mm; Width: 2999.99 mm

# IfcSlab: Strootplaat 3, Strootplaat 14:Strootplaat 3:1631362
In: 00 begane grond
Type - PredefinedType: FLOOR; Material: 00_PBT_MAT_beton prefab
Type - Pset_ProductRequirements - Category: Floors
Type - Pset_QuantityTakeOff - Reference: Strootplaat 14:Strootplaat 3
Type - Pset_ReinforcementBarPitchOfSlab - Description: stootplaat d=250; Reference: Strootplaat 14:Strootplaat 3
Type - Pset_SlabCommon - IsExternal: no; Reference: Strootplaat 14:Strootplaat 3
Type - Pset_Pieters - Omschrijving: stootplaat d=250
Pset_SlabCommon - PitchAngle: 3 deg
Phasing - Phase Created: Nieuw
Pset_Pieters - Naam: Strootplaat 14: Strootplaat 3; Type: Strootplaat 14: Strootplaat 3; Fase: gecreeerd: Nieuw; Verdieping: Level: PEIL=NAP
BaseQuantities - GrossArea: 0.2375 m2; NetArea: 7.67499 m2; GrossVolume: 712.498 m3; NetVolume: 0.712499 m3; Perimeter: 2400 mm; Width: 2999.99 mm

# IfcSlab: Strootplaat 3, Strootplaat 15:Strootplaat 3:1634312
In: 00 begane grond
Type - PredefinedType: FLOOR; Material: 00_PBT_MAT_beton prefab
Type - Pset_ProductRequirements - Category: Floors
Type - Pset_QuantityTakeOff - Reference: Strootplaat 15:Strootplaat 3
Type - Pset_ReinforcementBarPitchOfSlab - Description: stootplaat d=200; Reference: Strootplaat 15:Strootplaat 3
Type - Pset_SlabCommon - IsExternal: no; Reference: Strootplaat 15:Strootplaat 3
Type - Pset_Pieters - Omschrijving: stootplaat d=200
Pset_SlabCommon - PitchAngle: 3 deg
Phasing - Phase Created: Nieuw
Pset_Pieters - Naam: Strootplaat 15: Strootplaat 3; Type: Strootplaat 15: Strootplaat 3; Fase: gecreeerd: Nieuw; Verdieping: Level: PEIL=NAP
BaseQuantities - GrossArea: 0.176994 m2; NetArea: 4.69386 m2; GrossVolume: 353.987 m3; NetVolume: 0.353987 m3; Perimeter: 2169.94 mm; Width: 1999.99 mm

# IfcSlab: Strootplaat 3, Strootplaat 16:Strootplaat 3:1634814
In: 00 begane grond
Type - PredefinedType: FLOOR; Material: 00_PBT_MAT_beton prefab
Type - Pset_ProductRequirements - Category: Floors
Type - Pset_QuantityTakeOff - Reference: Strootplaat 16:Strootplaat 3
Type - Pset_ReinforcementBarPitchOfSlab - Description: stootplaat d=200; Reference: Strootplaat 16:Strootplaat 3
Type - Pset_SlabCommon - IsExternal: no; Reference: Strootplaat 16:Strootplaat 3
Type - Pset_Pieters - Omschrijving: stootplaat d=200
Pset_SlabCommon - PitchAngle: 3 deg
Phasing - Phase Created: Nieuw
Pset_Pieters - Naam: Strootplaat 16: Strootplaat 3; Type: Strootplaat 16: Strootplaat 3; Fase: gecreeerd: Nieuw; Verdieping: Level: PEIL=NAP
BaseQuantities - GrossArea: 0.176994 m2; NetArea: 4.69386 m2; GrossVolume: 353.987 m3; NetVolume: 0.353987 m3; Perimeter: 2169.94 mm; Width: 1999.99 mm

# IfcSlab: Strootplaat 3, Strootplaat 17:Strootplaat 3:1635253
In: 00 begane grond
Type - PredefinedType: FLOOR; Material: 00_PBT_MAT_beton prefab
Type - Pset_ProductRequirements - Category: Floors
Type - Pset_QuantityTakeOff - Reference: Strootplaat 17:Strootplaat 3
Type - Pset_ReinforcementBarPitchOfSlab - Description: stootplaat d=200; Reference: Strootplaat 17:Strootplaat 3
Type - Pset_SlabCommon - IsExternal: no; Reference: Strootplaat 17:Strootplaat 3
Type - Pset_Pieters - Omschrijving: stootplaat d=200
Pset_SlabCommon - PitchAngle: 3 deg
Phasing - Phase Created: Nieuw
Pset_Pieters - Naam: Strootplaat 17: Strootplaat 3; Type: Strootplaat 17: Strootplaat 3; Fase: gecreeerd: Nieuw; Verdieping: Level: PEIL=NAP
BaseQuantities - GrossArea: 0.2375 m2; NetArea: 7.67499 m2; GrossVolume: 712.499 m3; NetVolume: 0.712499 m3; Perimeter: 2400 mm; Width: 3000 mm

# IfcSlab: Strootplaat 3, Strootplaat 18:Strootplaat 3:1635280
In: 00 begane grond
Type - PredefinedType: FLOOR; Material: 00_PBT_MAT_beton prefab
Type - Pset_ProductRequirements - Category: Floors
Type - Pset_QuantityTakeOff - Reference: Strootplaat 18:Strootplaat 3
Type - Pset_ReinforcementBarPitchOfSlab - Description: stootplaat d=200; Reference: Strootplaat 18:Strootplaat 3
Type - Pset_SlabCommon - IsExternal: no; Reference: Strootplaat 18:Strootplaat 3
Type - Pset_Pieters - Omschrijving: stootplaat d=200
Pset_SlabCommon - PitchAngle: 3 deg
Phasing - Phase Created: Nieuw
Pset_Pieters - Naam: Strootplaat 18: Strootplaat 3; Type: Strootplaat 18: Strootplaat 3; Fase: gecreeerd: Nieuw; Verdieping: Level: PEIL=NAP
BaseQuantities - GrossArea: 0.2375 m2; NetArea: 7.67499 m2; GrossVolume: 712.499 m3; NetVolume: 0.712499 m3; Perimeter: 2400 mm; Width: 3000 mm

# IfcSlab: Strootplaat 3, Strootplaat 19:Strootplaat 3:1635293
In: 00 begane grond
Type - PredefinedType: FLOOR; Material: 00_PBT_MAT_beton prefab
Type - Pset_ProductRequirements - Category: Floors
Type - Pset_QuantityTakeOff - Reference: Strootplaat 19:Strootplaat 3
Type - Pset_ReinforcementBarPitchOfSlab - Description: stootplaat d=200; Reference: Strootplaat 19:Strootplaat 3
Type - Pset_SlabCommon - IsExternal: no; Reference: Strootplaat 19:Strootplaat 3
Type - Pset_Pieters - Omschrijving: stootplaat d=200
Pset_SlabCommon - PitchAngle: 3 deg
Phasing - Phase Created: Nieuw
Pset_Pieters - Naam: Strootplaat 19: Strootplaat 3; Type: Strootplaat 19: Strootplaat 3; Fase: gecreeerd: Nieuw; Verdieping: Level: PEIL=NAP
BaseQuantities - GrossArea: 0.2375 m2; NetArea: 7.67499 m2; GrossVolume: 712.499 m3; NetVolume: 0.712499 m3; Perimeter: 2400 mm; Width: 3000 mm

# IfcSlab: Strootplaat 3, Strootplaat 1:Strootplaat 3:1522556
In: 00 begane grond
Type - PredefinedType: FLOOR; Material: 00_PBT_MAT_beton prefab
Type - Pset_ProductRequirements - Category: Floors
Type - Pset_QuantityTakeOff - Reference: Strootplaat 1:Strootplaat 3
Type - Pset_ReinforcementBarPitchOfSlab - Reference: Strootplaat 1:Strootplaat 3
Type - Pset_SlabCommon - IsExternal: no; Reference: Strootplaat 1:Strootplaat 3
Pset_QuantityTakeOff - sets with these values: 2
Pset_SlabCommon - PitchAngle: 3 deg
Phasing - Phase Created: Nieuw
Pset_Pieters - Naam: Strootplaat 1: Strootplaat 3; Type: Strootplaat 1: Strootplaat 3; Fase: gecreeerd: Nieuw; Verdieping: Level: PEIL=NAP
BaseQuantities - GrossArea: 0.177 m2; NetArea: 4.694 m2; GrossVolume: 354 m3; NetVolume: 0.354 m3; Perimeter: 2170 mm; Width: 2000 mm

# IfcSlab: Strootplaat 3, Strootplaat 20:Strootplaat 3:1635306
In: 00 begane grond
Type - PredefinedType: FLOOR; Material: 00_PBT_MAT_beton prefab
Type - Pset_ProductRequirements - Category: Floors
Type - Pset_QuantityTakeOff - Reference: Strootplaat 20:Strootplaat 3
Type - Pset_ReinforcementBarPitchOfSlab - Description: stootplaat d=200; Reference: Strootplaat 20:Strootplaat 3
Type - Pset_SlabCommon - IsExternal: no; Reference: Strootplaat 20:Strootplaat 3
Type - Pset_Pieters - Omschrijving: stootplaat d=200
Pset_SlabCommon - PitchAngle: 3 deg
Phasing - Phase Created: Nieuw
Pset_Pieters - Naam: Strootplaat 20: Strootplaat 3; Type: Strootplaat 20: Strootplaat 3; Fase: gecreeerd: Nieuw; Verdieping: Level: PEIL=NAP
BaseQuantities - GrossArea: 0.2375 m2; NetArea: 7.67499 m2; GrossVolume: 712.499 m3; NetVolume: 0.712499 m3; Perimeter: 2400 mm; Width: 3000 mm

# IfcSlab: Strootplaat 3, Strootplaat 21:Strootplaat 3:1635319
In: 00 begane grond
Type - PredefinedType: FLOOR; Material: 00_PBT_MAT_beton prefab
Type - Pset_ProductRequirements - Category: Floors
Type - Pset_QuantityTakeOff - Reference: Strootplaat 21:Strootplaat 3
Type - Pset_ReinforcementBarPitchOfSlab - Description: stootplaat d=200; Reference: Strootplaat 21:Strootplaat 3
Type - Pset_SlabCommon - IsExternal: no; Reference: Strootplaat 21:Strootplaat 3
Type - Pset_Pieters - Omschrijving: stootplaat d=200
Pset_SlabCommon - PitchAngle: 3 deg
Phasing - Phase Created: Nieuw
Pset_Pieters - Naam: Strootplaat 21: Strootplaat 3; Type: Strootplaat 21: Strootplaat 3; Fase: gecreeerd: Nieuw; Verdieping: Level: PEIL=NAP
BaseQuantities - GrossArea: 0.2375 m2; NetArea: 7.67499 m2; GrossVolume: 712.499 m3; NetVolume: 0.712499 m3; Perimeter: 2400 mm; Width: 3000 mm

# IfcSlab: Strootplaat 3, Strootplaat 22:Strootplaat 3:1635332
In: 00 begane grond
Type - PredefinedType: FLOOR; Material: 00_PBT_MAT_beton prefab
Type - Pset_ProductRequirements - Category: Floors
Type - Pset_QuantityTakeOff - Reference: Strootplaat 22:Strootplaat 3
Type - Pset_ReinforcementBarPitchOfSlab - Description: stootplaat d=200; Reference: Strootplaat 22:Strootplaat 3
Type - Pset_SlabCommon - IsExternal: no; Reference: Strootplaat 22:Strootplaat 3
Type - Pset_Pieters - Omschrijving: stootplaat d=200
Pset_SlabCommon - PitchAngle: 3 deg
Phasing - Phase Created: Nieuw
Pset_Pieters - Naam: Strootplaat 22: Strootplaat 3; Type: Strootplaat 22: Strootplaat 3; Fase: gecreeerd: Nieuw; Verdieping: Level: PEIL=NAP
BaseQuantities - GrossArea: 0.176994 m2; NetArea: 4.69386 m2; GrossVolume: 353.987 m3; NetVolume: 0.353987 m3; Perimeter: 2169.94 mm; Width: 2000 mm

# IfcSlab: Strootplaat 3, Strootplaat 23:Strootplaat 3:1635345
In: 00 begane grond
Type - PredefinedType: FLOOR; Material: 00_PBT_MAT_beton prefab
Type - Pset_ProductRequirements - Category: Floors
Type - Pset_QuantityTakeOff - Reference: Strootplaat 23:Strootplaat 3
Type - Pset_ReinforcementBarPitchOfSlab - Description: stootplaat d=200; Reference: Strootplaat 23:Strootplaat 3
Type - Pset_SlabCommon - IsExternal: no; Reference: Strootplaat 23:Strootplaat 3
Type - Pset_Pieters - Omschrijving: stootplaat d=200
Pset_SlabCommon - PitchAngle: 3 deg
Phasing - Phase Created: Nieuw
Pset_Pieters - Naam: Strootplaat 23: Strootplaat 3; Type: Strootplaat 23: Strootplaat 3; Fase: gecreeerd: Nieuw; Verdieping: Level: PEIL=NAP
BaseQuantities - GrossArea: 0.176994 m2; NetArea: 4.69386 m2; GrossVolume: 353.987 m3; NetVolume: 0.353987 m3; Perimeter: 2169.94 mm; Width: 2000 mm

# IfcSlab: Strootplaat 3, Strootplaat 24:Strootplaat 3:1698294
In: 00 begane grond
Type - PredefinedType: FLOOR; Material: 00_PBT_MAT_beton prefab
Type - Pset_ProductRequirements - Category: Floors
Type - Pset_QuantityTakeOff - Reference: Strootplaat 24:Strootplaat 3
Type - Pset_ReinforcementBarPitchOfSlab - Description: stootplaat d=250; Reference: Strootplaat 24:Strootplaat 3
Type - Pset_SlabCommon - IsExternal: no; Reference: Strootplaat 24:Strootplaat 3
Type - Pset_Pieters - Omschrijving: stootplaat d=250
Pset_SlabCommon - PitchAngle: 0.0785219 deg
Phasing - Phase Created: Nieuw
Pset_Pieters - Naam: Strootplaat 24: Strootplaat 3; Type: Strootplaat 24: Strootplaat 3; Fase: gecreeerd: Nieuw; Verdieping: Level: PEIL=NAP
BaseQuantities - GrossArea: 2.85 m2; NetArea: 7.6816 m2; GrossVolume: 712.499 m3; NetVolume: 0.712499 m3; Perimeter: 7926.41 mm; Width: 250 mm

# IfcSlab: Strootplaat 3, Strootplaat 25:Strootplaat 3:1698558
In: 00 begane grond
Type - PredefinedType: FLOOR; Material: 00_PBT_MAT_beton prefab
Type - Pset_ProductRequirements - Category: Floors
Type - Pset_QuantityTakeOff - Reference: Strootplaat 25:Strootplaat 3
Type - Pset_ReinforcementBarPitchOfSlab - Description: stootplaat d=250; Reference: Strootplaat 25:Strootplaat 3
Type - Pset_SlabCommon - IsExternal: no; Reference: Strootplaat 25:Strootplaat 3
Type - Pset_Pieters - Omschrijving: stootplaat d=250
Pset_SlabCommon - PitchAngle: 0.0785219 deg
Phasing - Phase Created: Nieuw
Pset_Pieters - Naam: Strootplaat 25: Strootplaat 3; Type: Strootplaat 25: Strootplaat 3; Fase: gecreeerd: Nieuw; Verdieping: Level: PEIL=NAP
BaseQuantities - GrossArea: 2.85 m2; NetArea: 7.6816 m2; GrossVolume: 712.499 m3; NetVolume: 0.712499 m3; Perimeter: 7926.41 mm; Width: 250 mm

# IfcSlab: Strootplaat 3, Strootplaat 26:Strootplaat 3:1698879
In: 00 begane grond
Type - PredefinedType: FLOOR; Material: 00_PBT_MAT_beton prefab
Type - Pset_ProductRequirements - Category: Floors
Type - Pset_QuantityTakeOff - Reference: Strootplaat 26:Strootplaat 3
Type - Pset_ReinforcementBarPitchOfSlab - Description: stootplaat d=250; Reference: Strootplaat 26:Strootplaat 3
Type - Pset_SlabCommon - IsExternal: no; Reference: Strootplaat 26:Strootplaat 3
Type - Pset_Pieters - Omschrijving: stootplaat d=250
Pset_SlabCommon - PitchAngle: 0.0785219 deg
Phasing - Phase Created: Nieuw
Pset_Pieters - Naam: Strootplaat 26: Strootplaat 3; Type: Strootplaat 26: Strootplaat 3; Fase: gecreeerd: Nieuw; Verdieping: Level: PEIL=NAP
BaseQuantities - GrossArea: 2.85 m2; NetArea: 7.6816 m2; GrossVolume: 712.499 m3; NetVolume: 0.712499 m3; Perimeter: 7926.41 mm; Width: 250 mm

# IfcSlab: Strootplaat 3, Strootplaat 27:Strootplaat 3:1698946
In: 00 begane grond
Type - PredefinedType: FLOOR; Material: 00_PBT_MAT_beton prefab
Type - Pset_ProductRequirements - Category: Floors
Type - Pset_QuantityTakeOff - Reference: Strootplaat 27:Strootplaat 3
Type - Pset_ReinforcementBarPitchOfSlab - Description: stootplaat d=250; Reference: Strootplaat 27:Strootplaat 3
Type - Pset_SlabCommon - IsExternal: no; Reference: Strootplaat 27:Strootplaat 3
Type - Pset_Pieters - Omschrijving: stootplaat d=250
Pset_SlabCommon - PitchAngle: 0.0785219 deg
Phasing - Phase Created: Nieuw
Pset_Pieters - Naam: Strootplaat 27: Strootplaat 3; Type: Strootplaat 27: Strootplaat 3; Fase: gecreeerd: Nieuw; Verdieping: Level: PEIL=NAP
BaseQuantities - GrossArea: 2.85 m2; NetArea: 7.6816 m2; GrossVolume: 712.499 m3; NetVolume: 0.712499 m3; Perimeter: 7926.41 mm; Width: 250 mm

# IfcSlab: Strootplaat 3, Strootplaat 28:Strootplaat 3:1697522
In: 00 begane grond
Type - PredefinedType: FLOOR; Material: 00_PBT_MAT_beton prefab
Type - Pset_ProductRequirements - Category: Floors
Type - Pset_QuantityTakeOff - Reference: Strootplaat 28:Strootplaat 3
Type - Pset_ReinforcementBarPitchOfSlab - Description: stootplaat d=250; Reference: Strootplaat 28:Strootplaat 3
Type - Pset_SlabCommon - IsExternal: no; Reference: Strootplaat 28:Strootplaat 3
Type - Pset_Pieters - Omschrijving: stootplaat d=250
Pset_SlabCommon - PitchAngle: 0.0785219 deg
Phasing - Phase Created: Nieuw
Pset_Pieters - Naam: Strootplaat 28: Strootplaat 3; Type: Strootplaat 28: Strootplaat 3; Fase: gecreeerd: Nieuw; Verdieping: Level: PEIL=NAP
BaseQuantities - GrossArea: 2.85 m2; NetArea: 7.6816 m2; GrossVolume: 712.499 m3; NetVolume: 0.712499 m3; Perimeter: 7926.41 mm; Width: 250 mm

# IfcSlab: Strootplaat 3, Strootplaat 29:Strootplaat 3:1744940
In: 00 begane grond
Type - PredefinedType: FLOOR; Material: 00_PBT_MAT_beton prefab
Type - Pset_ProductRequirements - Category: Floors
Type - Pset_QuantityTakeOff - Reference: Strootplaat 29:Strootplaat 3
Type - Pset_ReinforcementBarPitchOfSlab - Description: stootplaat d=200; Reference: Strootplaat 29:Strootplaat 3
Type - Pset_SlabCommon - IsExternal: no; Reference: Strootplaat 29:Strootplaat 3
Type - Pset_Pieters - Omschrijving: stootplaat d=200
Pset_SlabCommon - PitchAngle: 0.0785219 deg
Phasing - Phase Created: Nieuw
Pset_Pieters - Naam: Strootplaat 29: Strootplaat 3; Type: Strootplaat 29: Strootplaat 3; Fase: gecreeerd: Nieuw; Verdieping: Level: PEIL=NAP
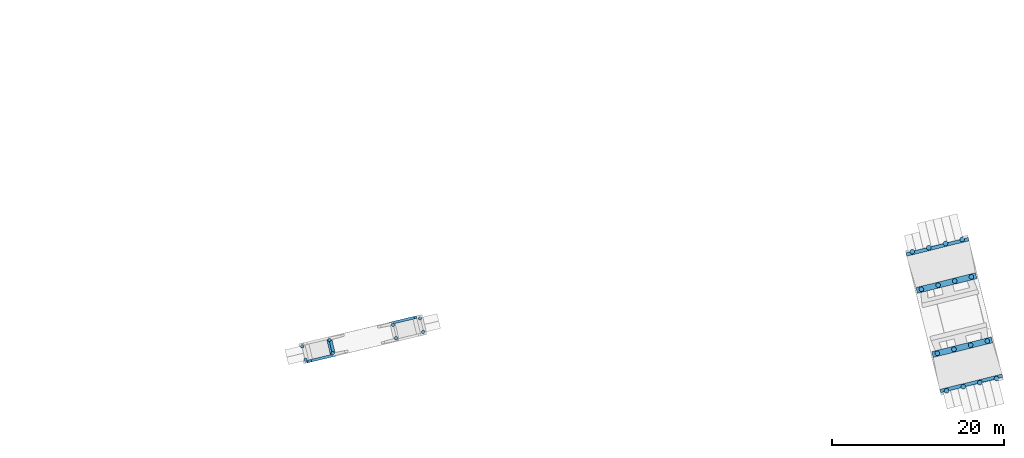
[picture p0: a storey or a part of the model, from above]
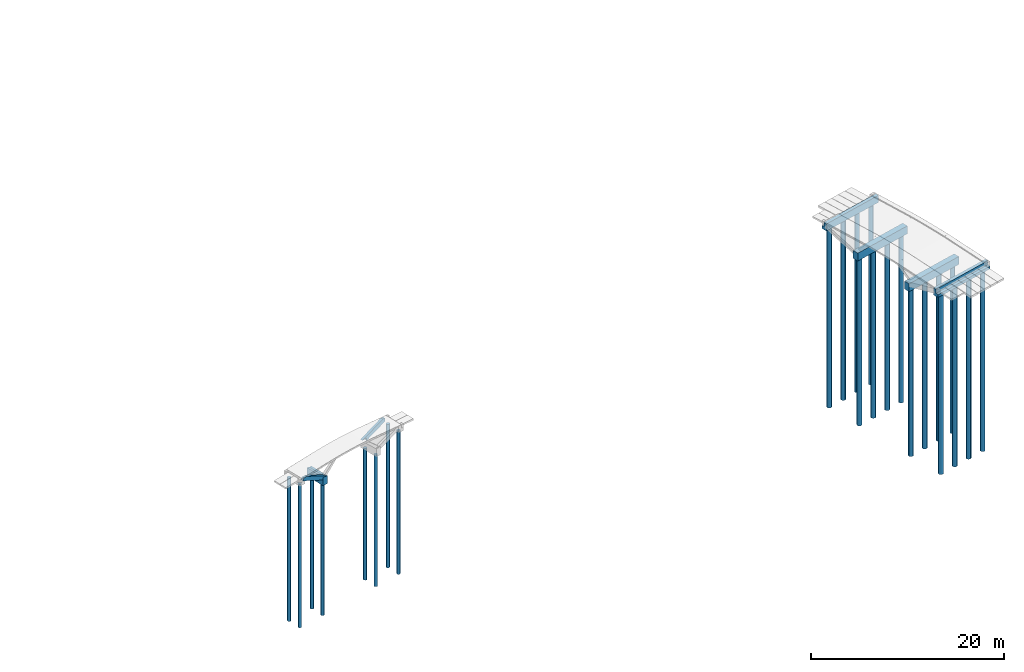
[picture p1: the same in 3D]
Properties of the parts of a building model (IFC2X3), part 2 of 2

# IfcSlab: Strootplaat 3, Strootplaat 29:Strootplaat 3:1744940
BaseQuantities - GrossArea: 2.85 m2; NetArea: 7.6816 m2; GrossVolume: 712.499 m3; NetVolume: 0.712499 m3; Perimeter: 7926.41 mm; Width: 250 mm

# IfcSlab: Strootplaat 3, Strootplaat 2:Strootplaat 3:1483665
In: 00 begane grond
Type - PredefinedType: FLOOR; Material: 00_PBT_MAT_beton prefab
Type - Pset_ProductRequirements - Category: Floors
Type - Pset_QuantityTakeOff - Reference: Strootplaat 2:Strootplaat 3
Type - Pset_ReinforcementBarPitchOfSlab - Description: stootplaat d=200; Reference: Strootplaat 2:Strootplaat 3
Type - Pset_SlabCommon - IsExternal: no; Reference: Strootplaat 2:Strootplaat 3
Type - Pset_Pieters - Omschrijving: stootplaat d=200
Pset_SlabCommon - PitchAngle: 3 deg
Phasing - Phase Created: Nieuw
Pset_Pieters - Naam: Strootplaat 2: Strootplaat 3; Type: Strootplaat 2: Strootplaat 3; Fase: gecreeerd: Nieuw; Verdieping: Level: PEIL=NAP
BaseQuantities - GrossArea: 0.177 m2; NetArea: 4.694 m2; GrossVolume: 354 m3; NetVolume: 0.354 m3; Perimeter: 2170 mm; Width: 2000 mm

# IfcSlab: Strootplaat 3, Strootplaat 30:Strootplaat 3:1697548
In: 00 begane grond
Type - PredefinedType: FLOOR; Material: 00_PBT_MAT_beton prefab
Type - Pset_ProductRequirements - Category: Floors
Type - Pset_QuantityTakeOff - Reference: Strootplaat 30:Strootplaat 3
Type - Pset_ReinforcementBarPitchOfSlab - Description: stootplaat d=200; Reference: Strootplaat 30:Strootplaat 3
Type - Pset_SlabCommon - IsExternal: no; Reference: Strootplaat 30:Strootplaat 3
Type - Pset_Pieters - Omschrijving: stootplaat d=200
Pset_SlabCommon - PitchAngle: 0.0785219 deg
Phasing - Phase Created: Nieuw
Pset_Pieters - Naam: Strootplaat 30: Strootplaat 3; Type: Strootplaat 30: Strootplaat 3; Fase: gecreeerd: Nieuw; Verdieping: Level: PEIL=NAP
BaseQuantities - GrossArea: 1.7 m2; NetArea: 4.54472 m2; GrossVolume: 339.999 m3; NetVolume: 0.339999 m3; Perimeter: 5723.63 mm; Width: 200 mm

# IfcSlab: Strootplaat 3, Strootplaat 31:Strootplaat 3:1744953
In: 00 begane grond
Type - PredefinedType: FLOOR; Material: 00_PBT_MAT_beton prefab
Type - Pset_ProductRequirements - Category: Floors
Type - Pset_QuantityTakeOff - Reference: Strootplaat 31:Strootplaat 3
Type - Pset_ReinforcementBarPitchOfSlab - Description: stootplaat d=200; Reference: Strootplaat 31:Strootplaat 3
Type - Pset_SlabCommon - IsExternal: no; Reference: Strootplaat 31:Strootplaat 3
Type - Pset_Pieters - Omschrijving: stootplaat d=200
Pset_SlabCommon - PitchAngle: 0.0785219 deg
Phasing - Phase Created: Nieuw
Pset_Pieters - Naam: Strootplaat 31: Strootplaat 3; Type: Strootplaat 31: Strootplaat 3; Fase: gecreeerd: Nieuw; Verdieping: Level: PEIL=NAP
BaseQuantities - GrossArea: 1.7 m2; NetArea: 4.54472 m2; GrossVolume: 339.999 m3; NetVolume: 0.339999 m3; Perimeter: 5723.63 mm; Width: 200 mm

# IfcSlab: Strootplaat 3, Strootplaat 32:Strootplaat 3:1744966
In: 00 begane grond
Type - PredefinedType: FLOOR; Material: 00_PBT_MAT_beton prefab
Type - Pset_ProductRequirements - Category: Floors
Type - Pset_QuantityTakeOff - Reference: Strootplaat 32:Strootplaat 3
Type - Pset_ReinforcementBarPitchOfSlab - Description: stootplaat d=200; Reference: Strootplaat 32:Strootplaat 3
Type - Pset_SlabCommon - IsExternal: no; Reference: Strootplaat 32:Strootplaat 3
Type - Pset_Pieters - Omschrijving: stootplaat d=200
Pset_SlabCommon - PitchAngle: 0.0785219 deg
Phasing - Phase Created: Nieuw
Pset_Pieters - Naam: Strootplaat 32: Strootplaat 3; Type: Strootplaat 32: Strootplaat 3; Fase: gecreeerd: Nieuw; Verdieping: Level: PEIL=NAP
BaseQuantities - GrossArea: 2.85 m2; NetArea: 7.6816 m2; GrossVolume: 712.499 m3; NetVolume: 0.712499 m3; Perimeter: 7926.41 mm; Width: 250 mm

# IfcSlab: Strootplaat 3, Strootplaat 33:Strootplaat 3:1744979
In: 00 begane grond
Type - PredefinedType: FLOOR; Material: 00_PBT_MAT_beton prefab
Type - Pset_ProductRequirements - Category: Floors
Type - Pset_QuantityTakeOff - Reference: Strootplaat 33:Strootplaat 3
Type - Pset_ReinforcementBarPitchOfSlab - Description: stootplaat d=200; Reference: Strootplaat 33:Strootplaat 3
Type - Pset_SlabCommon - IsExternal: no; Reference: Strootplaat 33:Strootplaat 3
Type - Pset_Pieters - Omschrijving: stootplaat d=200
Pset_SlabCommon - PitchAngle: 0.0785219 deg
Phasing - Phase Created: Nieuw
Pset_Pieters - Naam: Strootplaat 33: Strootplaat 3; Type: Strootplaat 33: Strootplaat 3; Fase: gecreeerd: Nieuw; Verdieping: Level: PEIL=NAP
BaseQuantities - GrossArea: 2.85 m2; NetArea: 7.6816 m2; GrossVolume: 712.499 m3; NetVolume: 0.712499 m3; Perimeter: 7926.41 mm; Width: 250 mm

# IfcSlab: Strootplaat 3, Strootplaat 34:Strootplaat 3:1744992
In: 00 begane grond
Type - PredefinedType: FLOOR; Material: 00_PBT_MAT_beton prefab
Type - Pset_ProductRequirements - Category: Floors
Type - Pset_QuantityTakeOff - Reference: Strootplaat 34:Strootplaat 3
Type - Pset_ReinforcementBarPitchOfSlab - Description: stootplaat d=200; Reference: Strootplaat 34:Strootplaat 3
Type - Pset_SlabCommon - IsExternal: no; Reference: Strootplaat 34:Strootplaat 3
Type - Pset_Pieters - Omschrijving: stootplaat d=200
Pset_SlabCommon - PitchAngle: 0.0785219 deg
Phasing - Phase Created: Nieuw
Pset_Pieters - Naam: Strootplaat 34: Strootplaat 3; Type: Strootplaat 34: Strootplaat 3; Fase: gecreeerd: Nieuw; Verdieping: Level: PEIL=NAP
BaseQuantities - GrossArea: 2.85 m2; NetArea: 7.6816 m2; GrossVolume: 712.499 m3; NetVolume: 0.712499 m3; Perimeter: 7926.41 mm; Width: 250 mm

# IfcSlab: Strootplaat 3, Strootplaat 35:Strootplaat 3:1745005
In: 00 begane grond
Type - PredefinedType: FLOOR; Material: 00_PBT_MAT_beton prefab
Type - Pset_ProductRequirements - Category: Floors
Type - Pset_QuantityTakeOff - Reference: Strootplaat 35:Strootplaat 3
Type - Pset_ReinforcementBarPitchOfSlab - Description: stootplaat d=200; Reference: Strootplaat 35:Strootplaat 3
Type - Pset_SlabCommon - IsExternal: no; Reference: Strootplaat 35:Strootplaat 3
Type - Pset_Pieters - Omschrijving: stootplaat d=200
Pset_SlabCommon - PitchAngle: 0.0785219 deg
Phasing - Phase Created: Nieuw
Pset_Pieters - Naam: Strootplaat 35: Strootplaat 3; Type: Strootplaat 35: Strootplaat 3; Fase: gecreeerd: Nieuw; Verdieping: Level: PEIL=NAP
BaseQuantities - GrossArea: 2.85 m2; NetArea: 7.6816 m2; GrossVolume: 712.499 m3; NetVolume: 0.712499 m3; Perimeter: 7926.41 mm; Width: 250 mm

# IfcSlab: Strootplaat 3, Strootplaat 36:Strootplaat 3:1745018
In: 00 begane grond
Type - PredefinedType: FLOOR; Material: 00_PBT_MAT_beton prefab
Type - Pset_ProductRequirements - Category: Floors
Type - Pset_QuantityTakeOff - Reference: Strootplaat 36:Strootplaat 3
Type - Pset_ReinforcementBarPitchOfSlab - Description: stootplaat d=200; Reference: Strootplaat 36:Strootplaat 3
Type - Pset_SlabCommon - IsExternal: no; Reference: Strootplaat 36:Strootplaat 3
Type - Pset_Pieters - Omschrijving: stootplaat d=200
Pset_SlabCommon - PitchAngle: 0.0785219 deg
Phasing - Phase Created: Nieuw
Pset_Pieters - Naam: Strootplaat 36: Strootplaat 3; Type: Strootplaat 36: Strootplaat 3; Fase: gecreeerd: Nieuw; Verdieping: Level: PEIL=NAP
BaseQuantities - GrossArea: 1.7 m2; NetArea: 4.54472 m2; GrossVolume: 339.999 m3; NetVolume: 0.339999 m3; Perimeter: 5723.63 mm; Width: 200 mm

# IfcSlab: Strootplaat 3, Strootplaat 37:Strootplaat 3:1733096
In: 00 begane grond
Type - PredefinedType: FLOOR; Material: 00_PBT_MAT_beton prefab
Type - Pset_ProductRequirements - Category: Floors
Type - Pset_QuantityTakeOff - Reference: Strootplaat 37:Strootplaat 3
Type - Pset_ReinforcementBarPitchOfSlab - Description: stootplaat d=200; Reference: Strootplaat 37:Strootplaat 3
Type - Pset_SlabCommon - IsExternal: no; Reference: Strootplaat 37:Strootplaat 3
Type - Pset_Pieters - Omschrijving: stootplaat d=200
Pset_SlabCommon - PitchAngle: 0.0785219 deg
Phasing - Phase Created: Nieuw
Pset_Pieters - Naam: Strootplaat 37: Strootplaat 3; Type: Strootplaat 37: Strootplaat 3; Fase: gecreeerd: Nieuw; Verdieping: Level: PEIL=NAP
BaseQuantities - GrossArea: 1.7 m2; NetArea: 4.54472 m2; GrossVolume: 339.999 m3; NetVolume: 0.339999 m3; Perimeter: 5723.63 mm; Width: 200 mm

# IfcSlab: Strootplaat 3, Strootplaat 3:Strootplaat 3:1546389
In: 00 begane grond
Type - PredefinedType: FLOOR; Material: 00_PBT_MAT_beton prefab
Type - Pset_ProductRequirements - Category: Floors
Type - Pset_QuantityTakeOff - Reference: Strootplaat 3:Strootplaat 3
Type - Pset_ReinforcementBarPitchOfSlab - Description: stootplaat d=200; Reference: Strootplaat 3:Strootplaat 3
Type - Pset_SlabCommon - IsExternal: no; Reference: Strootplaat 3:Strootplaat 3
Type - Pset_Pieters - Omschrijving: stootplaat d=200
Pset_SlabCommon - PitchAngle: 3 deg
Phasing - Phase Created: Nieuw
Pset_Pieters - Naam: Strootplaat 3: Strootplaat 3; Type: Strootplaat 3: Strootplaat 3; Fase: gecreeerd: Nieuw; Verdieping: Level: PEIL=NAP
BaseQuantities - GrossArea: 0.198 m2; NetArea: 5.156 m2; GrossVolume: 396 m3; NetVolume: 0.396 m3; Perimeter: 2380 mm; Width: 2000 mm

# IfcSlab: Strootplaat 3, Strootplaat 4:Strootplaat 3:1483762
In: 00 begane grond
Type - PredefinedType: FLOOR; Material: 00_PBT_MAT_beton prefab
Type - Pset_ProductRequirements - Category: Floors
Type - Pset_QuantityTakeOff - Reference: Strootplaat 4:Strootplaat 3
Type - Pset_ReinforcementBarPitchOfSlab - Reference: Strootplaat 4:Strootplaat 3
Type - Pset_SlabCommon - IsExternal: no; Reference: Strootplaat 4:Strootplaat 3
Pset_QuantityTakeOff - sets with these values: 2
Pset_SlabCommon - PitchAngle: 3 deg
Phasing - Phase Created: Nieuw
Pset_Pieters - Naam: Strootplaat 4: Strootplaat 3; Type: Strootplaat 4: Strootplaat 3; Fase: gecreeerd: Nieuw; Verdieping: Level: PEIL=NAP
BaseQuantities - GrossArea: 0.177 m2; NetArea: 4.694 m2; GrossVolume: 353.999 m3; NetVolume: 0.354 m3; Perimeter: 2170 mm; Width: 2000 mm

# IfcSlab: Strootplaat 3, Strootplaat 5:Strootplaat 3:1547818
In: 00 begane grond
Type - PredefinedType: FLOOR; Material: 00_PBT_MAT_beton prefab
Type - Pset_ProductRequirements - Category: Floors
Type - Pset_QuantityTakeOff - Reference: Strootplaat 5:Strootplaat 3
Type - Pset_ReinforcementBarPitchOfSlab - Description: stootplaat d=200; Reference: Strootplaat 5:Strootplaat 3
Type - Pset_SlabCommon - IsExternal: no; Reference: Strootplaat 5:Strootplaat 3
Type - Pset_Pieters - Omschrijving: stootplaat d=200
Pset_SlabCommon - PitchAngle: 3 deg
Phasing - Phase Created: Nieuw
Pset_Pieters - Naam: Strootplaat 5: Strootplaat 3; Type: Strootplaat 5: Strootplaat 3; Fase: gecreeerd: Nieuw; Verdieping: Level: PEIL=NAP
BaseQuantities - GrossArea: 0.198 m2; NetArea: 5.156 m2; GrossVolume: 396 m3; NetVolume: 0.396 m3; Perimeter: 2380 mm; Width: 2000 mm

# IfcSlab: Strootplaat 3, Strootplaat 6:Strootplaat 3:1547924
In: 00 begane grond
Type - PredefinedType: FLOOR; Material: 00_PBT_MAT_beton prefab
Type - Pset_ProductRequirements - Category: Floors
Type - Pset_QuantityTakeOff - Reference: Strootplaat 6:Strootplaat 3
Type - Pset_ReinforcementBarPitchOfSlab - Description: stootplaat d=200; Reference: Strootplaat 6:Strootplaat 3
Type - Pset_SlabCommon - IsExternal: no; Reference: Strootplaat 6:Strootplaat 3
Type - Pset_Pieters - Omschrijving: stootplaat d=200
Pset_SlabCommon - PitchAngle: 3 deg
Phasing - Phase Created: Nieuw
Pset_Pieters - Naam: Strootplaat 6: Strootplaat 3; Type: Strootplaat 6: Strootplaat 3; Fase: gecreeerd: Nieuw; Verdieping: Level: PEIL=NAP
BaseQuantities - GrossArea: 0.198 m2; NetArea: 5.156 m2; GrossVolume: 396 m3; NetVolume: 0.396 m3; Perimeter: 2380 mm; Width: 2000 mm

# IfcSlab: Strootplaat 3, Strootplaat 7:Strootplaat 3:1566150
In: 00 begane grond
Type - PredefinedType: FLOOR; Material: 00_PBT_MAT_beton prefab
Type - Pset_ProductRequirements - Category: Floors
Type - Pset_QuantityTakeOff - Reference: Strootplaat 7:Strootplaat 3
Type - Pset_ReinforcementBarPitchOfSlab - Description: stootplaat d=200; Reference: Strootplaat 7:Strootplaat 3
Type - Pset_SlabCommon - IsExternal: no; Reference: Strootplaat 7:Strootplaat 3
Type - Pset_Pieters - Omschrijving: stootplaat d=200
Pset_SlabCommon - PitchAngle: 3 deg
Phasing - Phase Created: Nieuw
Pset_Pieters - Naam: Strootplaat 7: Strootplaat 3; Type: Strootplaat 7: Strootplaat 3; Fase: gecreeerd: Nieuw; Verdieping: Level: PEIL=NAP
BaseQuantities - GrossArea: 0.198 m2; NetArea: 5.156 m2; GrossVolume: 396 m3; NetVolume: 0.396 m3; Perimeter: 2380 mm; Width: 2000 mm

# IfcSlab: Strootplaat 3, Strootplaat 8:Strootplaat 3:1566163
In: 00 begane grond
Type - PredefinedType: FLOOR; Material: 00_PBT_MAT_beton prefab
Type - Pset_ProductRequirements - Category: Floors
Type - Pset_QuantityTakeOff - Reference: Strootplaat 8:Strootplaat 3
Type - Pset_ReinforcementBarPitchOfSlab - Description: stootplaat d=200; Reference: Strootplaat 8:Strootplaat 3
Type - Pset_SlabCommon - IsExternal: no; Reference: Strootplaat 8:Strootplaat 3
Type - Pset_Pieters - Omschrijving: stootplaat d=200
Pset_SlabCommon - PitchAngle: 3 deg
Phasing - Phase Created: Nieuw
Pset_Pieters - Naam: Strootplaat 8: Strootplaat 3; Type: Strootplaat 8: Strootplaat 3; Fase: gecreeerd: Nieuw; Verdieping: Level: PEIL=NAP
BaseQuantities - GrossArea: 0.198 m2; NetArea: 5.156 m2; GrossVolume: 396 m3; NetVolume: 0.396 m3; Perimeter: 2380 mm; Width: 2000 mm

# IfcSlab: Strootplaat 3, Strootplaat 9:Strootplaat 3:1566176
In: 00 begane grond
Type - PredefinedType: FLOOR; Material: 00_PBT_MAT_beton prefab
Type - Pset_ProductRequirements - Category: Floors
Type - Pset_QuantityTakeOff - Reference: Strootplaat 9:Strootplaat 3
Type - Pset_ReinforcementBarPitchOfSlab - Description: stootplaat d=200; Reference: Strootplaat 9:Strootplaat 3
Type - Pset_SlabCommon - IsExternal: no; Reference: Strootplaat 9:Strootplaat 3
Type - Pset_Pieters - Omschrijving: stootplaat d=200
Pset_SlabCommon - PitchAngle: 3 deg
Phasing - Phase Created: Nieuw
Pset_Pieters - Naam: Strootplaat 9: Strootplaat 3; Type: Strootplaat 9: Strootplaat 3; Fase: gecreeerd: Nieuw; Verdieping: Level: PEIL=NAP
BaseQuantities - GrossArea: 0.198 m2; NetArea: 5.156 m2; GrossVolume: 396 m3; NetVolume: 0.396 m3; Perimeter: 2380 mm; Width: 2000 mm

# IfcSlab: Strootplaat 3, Strootplaat1:Strootplaat 3:1482772
In: 00 begane grond
Type - PredefinedType: FLOOR; Material: 00_PBT_MAT_beton prefab
Type - Pset_ProductRequirements - Category: Floors
Type - Pset_QuantityTakeOff - Reference: Strootplaat1:Strootplaat 3
Type - Pset_ReinforcementBarPitchOfSlab - Reference: Strootplaat1:Strootplaat 3
Type - Pset_SlabCommon - IsExternal: no; Reference: Strootplaat1:Strootplaat 3
Pset_QuantityTakeOff - sets with these values: 2
Pset_SlabCommon - PitchAngle: 3 deg
Phasing - Phase Created: Nieuw
Pset_Pieters - Naam: Strootplaat1: Strootplaat 3; Type: Strootplaat1: Strootplaat 3; Fase: gecreeerd: Nieuw; Verdieping: Level: NAP
BaseQuantities - GrossArea: 0.177 m2; NetArea: 4.694 m2; GrossVolume: 353.999 m3; NetVolume: 0.354 m3; Perimeter: 2170 mm; Width: 2000 mm

# IfcSlab: Structural Foundations 1, Structural Foundations 1:Structural Foundations 1:1480483
In: 00 begane grond
Type - PredefinedType: FLOOR; Material: 00_PBT_MAT_beton t.p.g.
Type - Pset_ProductRequirements - Category: Structural Foundations
Type - Pset_QuantityTakeOff - Reference: Structural Foundations 1:Structural Foundations 1
Type - Pset_ReinforcementBarPitchOfSlab - Reference: Structural Foundations 1:Structural Foundations 1
Type - Pset_SlabCommon - Reference: Structural Foundations 1:Structural Foundations 1; IsExternal: no
Pset_QuantityTakeOff - sets with these values: 2
Pset_SlabCommon - PitchAngle: 0 deg
Phasing - Phase Created: Nieuw
Pset_Pieters - Naam: Structural Foundations 1: Structural Foundations 1; Type: Structural Foundations 1: Structural Foundations 1; Fase: gecreeerd: Nieuw
BaseQuantities - NetArea: 0.724744 m2; NetVolume: 0.0405201 m3

# IfcSlab: Structural Foundations 1, Structural Foundations 2:Structural Foundations 1:1499277
In: 00 begane grond
Type - PredefinedType: FLOOR; Material: 00_PBT_MAT_beton t.p.g.
Type - Pset_ProductRequirements - Category: Structural Foundations
Type - Pset_QuantityTakeOff - Reference: Structural Foundations 2:Structural Foundations 1
Type - Pset_ReinforcementBarPitchOfSlab - Reference: Structural Foundations 2:Structural Foundations 1
Type - Pset_SlabCommon - IsExternal: no; Reference: Structural Foundations 2:Structural Foundations 1
Pset_QuantityTakeOff - sets with these values: 2
Pset_SlabCommon - PitchAngle: 0 deg
Phasing - Phase Created: Nieuw
Pset_Pieters - Naam: Structural Foundations 2: Structural Foundations 1; Type: Structural Foundations 2: Structural Foundations 1; Fase: gecreeerd: Nieuw
BaseQuantities - NetArea: 0.724749 m2; NetVolume: 0.0405204 m3

# IfcSlab: Structural Foundations 1, Structural Foundations 3:Structural Foundations 1:1498229
In: 00 begane grond
Type - PredefinedType: FLOOR; Material: 00_PBT_MAT_beton t.p.g.
Type - Pset_ProductRequirements - Category: Structural Foundations
Type - Pset_QuantityTakeOff - Reference: Structural Foundations 3:Structural Foundations 1
Type - Pset_ReinforcementBarPitchOfSlab - Reference: Structural Foundations 3:Structural Foundations 1
Type - Pset_SlabCommon - IsExternal: no; Reference: Structural Foundations 3:Structural Foundations 1
Pset_QuantityTakeOff - sets with these values: 2
Pset_SlabCommon - PitchAngle: 0 deg
Phasing - Phase Created: Nieuw
Pset_Pieters - Naam: Structural Foundations 3: Structural Foundations 1; Type: Structural Foundations 3: Structural Foundations 1; Fase: gecreeerd: Nieuw
BaseQuantities - NetArea: 0.724744 m2; NetVolume: 0.0405201 m3

# IfcSlab: Structural Foundations 1, Structural Foundations 4:Structural Foundations 1:1498242
In: 00 begane grond
Type - PredefinedType: FLOOR; Material: 00_PBT_MAT_beton t.p.g.
Type - Pset_ProductRequirements - Category: Structural Foundations
Type - Pset_QuantityTakeOff - Reference: Structural Foundations 4:Structural Foundations 1
Type - Pset_ReinforcementBarPitchOfSlab - Reference: Structural Foundations 4:Structural Foundations 1
Type - Pset_SlabCommon - IsExternal: no; Reference: Structural Foundations 4:Structural Foundations 1
Pset_QuantityTakeOff - sets with these values: 2
Pset_SlabCommon - PitchAngle: 0 deg
Phasing - Phase Created: Nieuw
Pset_Pieters - Naam: Structural Foundations 4: Structural Foundations 1; Type: Structural Foundations 4: Structural Foundations 1; Fase: gecreeerd: Nieuw
BaseQuantities - NetArea: 0.724744 m2; NetVolume: 0.0405201 m3

# IfcSlab: brug 4 nokje aan funderingsbalk, brug 4 nokje aan funderingsbalk1:brug 4 nokje aan funderingsbalk:1631411
In: 00 begane grond
Type - PredefinedType: FLOOR; Material: 00_PBT_MAT_beton t.p.g.
Type - Pset_ProductRequirements - Category: Structural Foundations
Type - Pset_QuantityTakeOff - Reference: brug 4 nokje aan funderingsbalk1:brug 4 nokje aan funderingsbalk
Type - Pset_ReinforcementBarPitchOfSlab - Reference: brug 4 nokje aan funderingsbalk1:brug 4 nokje aan funderingsbalk
Type - Pset_SlabCommon - IsExternal: no; Reference: brug 4 nokje aan funderingsbalk1:brug 4 nokje aan funderingsbalk
Pset_QuantityTakeOff - sets with these values: 2
Pset_SlabCommon - PitchAngle: 0 deg
Phasing - Phase Created: Nieuw
Pset_Pieters - Naam: brug 4 nokje aan funderingsbalk1: brug 4 nokje aan funderingsbalk; Type: brug 4 nokje aan funderingsbalk1: brug 4 nokje aan funderingsbalk; Fase: gecreeerd: Nieuw
BaseQuantities - NetArea: 1.45651 m2; NetVolume: 0.108596 m3

# IfcSlab: brug 4 nokje aan funderingsbalk, brug 4 nokje aan funderingsbalk3:brug 4 nokje aan funderingsbalk:1654957
In: 00 begane grond
Type - PredefinedType: FLOOR; Material: 00_PBT_MAT_beton t.p.g.
Type - Pset_ProductRequirements - Category: Structural Foundations
Type - Pset_QuantityTakeOff - Reference: brug 4 nokje aan funderingsbalk3:brug 4 nokje aan funderingsbalk
Type - Pset_ReinforcementBarPitchOfSlab - Reference: brug 4 nokje aan funderingsbalk3:brug 4 nokje aan funderingsbalk
Type - Pset_SlabCommon - IsExternal: no; Reference: brug 4 nokje aan funderingsbalk3:brug 4 nokje aan funderingsbalk
Pset_QuantityTakeOff - sets with these values: 2
Pset_SlabCommon - PitchAngle: 0 deg
Phasing - Phase Created: Nieuw
Pset_Pieters - Naam: brug 4 nokje aan funderingsbalk3: brug 4 nokje aan funderingsbalk; Type: brug 4 nokje aan funderingsbalk3: brug 4 nokje aan funderingsbalk; Fase: gecreeerd: Nieuw
BaseQuantities - NetArea: 0.907762 m2; NetVolume: 0.054255 m3

# IfcSlab: brug 4 nokje aan funderingsbalk, brug 4 nokje aan funderingsbalk4:brug 4 nokje aan funderingsbalk:1654858
In: 00 begane grond
Type - PredefinedType: FLOOR; Material: 00_PBT_MAT_beton t.p.g.
Type - Pset_ProductRequirements - Category: Structural Foundations
Type - Pset_QuantityTakeOff - Reference: brug 4 nokje aan funderingsbalk4:brug 4 nokje aan funderingsbalk
Type - Pset_ReinforcementBarPitchOfSlab - Reference: brug 4 nokje aan funderingsbalk4:brug 4 nokje aan funderingsbalk
Type - Pset_SlabCommon - IsExternal: no; Reference: brug 4 nokje aan funderingsbalk4:brug 4 nokje aan funderingsbalk
Pset_QuantityTakeOff - sets with these values: 2
Pset_SlabCommon - PitchAngle: 0 deg
Phasing - Phase Created: Nieuw
Pset_Pieters - Naam: brug 4 nokje aan funderingsbalk4: brug 4 nokje aan funderingsbalk; Type: brug 4 nokje aan funderingsbalk4: brug 4 nokje aan funderingsbalk; Fase: gecreeerd: Nieuw
BaseQuantities - NetArea: 0.907762 m2; NetVolume: 0.054255 m3

# IfcSlab: brug 4 nokje aan funderingsbalk, brug 4 nokje aan funderingsbalk5:brug 4 nokje aan funderingsbalk:1827470
In: 00 begane grond
Type - PredefinedType: FLOOR; Material: 00_PBT_MAT_beton t.p.g.
Type - Pset_ProductRequirements - Category: Structural Foundations
Type - Pset_QuantityTakeOff - Reference: brug 4 nokje aan funderingsbalk5:brug 4 nokje aan funderingsbalk
Type - Pset_ReinforcementBarPitchOfSlab - Reference: brug 4 nokje aan funderingsbalk5:brug 4 nokje aan funderingsbalk
Type - Pset_SlabCommon - IsExternal: no; Reference: brug 4 nokje aan funderingsbalk5:brug 4 nokje aan funderingsbalk
Pset_QuantityTakeOff - sets with these values: 2
Pset_SlabCommon - PitchAngle: 0 deg
Phasing - Phase Created: Nieuw
Pset_Pieters - Naam: brug 4 nokje aan funderingsbalk5: brug 4 nokje aan funderingsbalk; Type: brug 4 nokje aan funderingsbalk5: brug 4 nokje aan funderingsbalk; Fase: gecreeerd: Nieuw
BaseQuantities - NetArea: 1.45569 m2; NetVolume: 0.108502 m3
